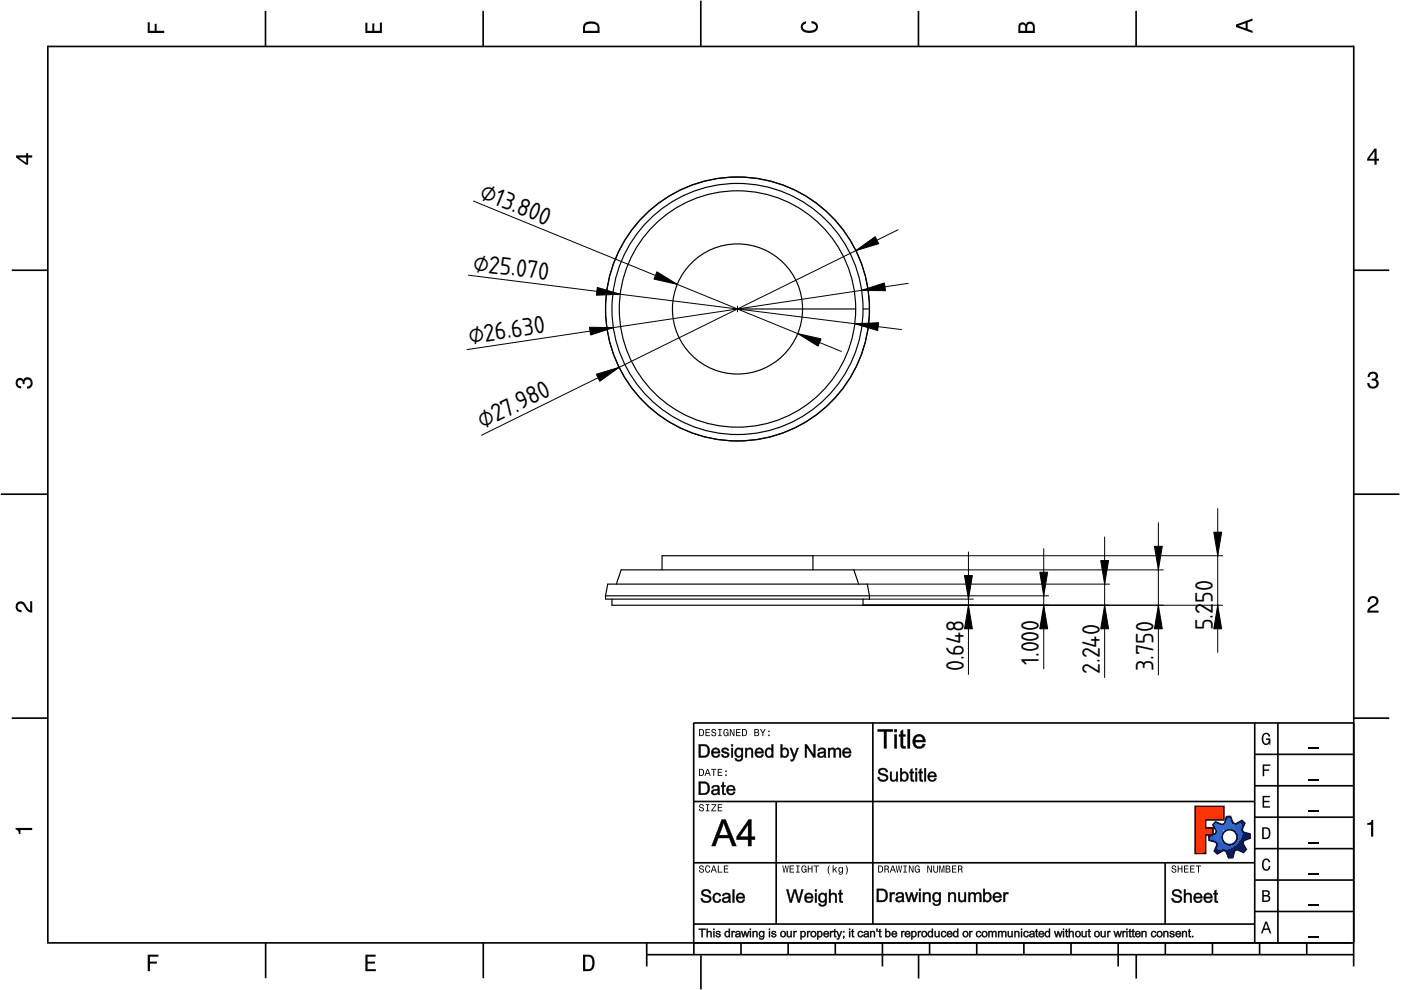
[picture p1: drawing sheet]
<svg xmlns="http://www.w3.org/2000/svg" width="297mm" height="210mm" viewBox="0 0 297 210" stroke-linecap="round" stroke-linejoin="round" font-family="sans-serif">
<defs><g id="words">
<g font-size="5">
<text x="101.5" y="41.9" transform="rotate(22 101.5 41.9)">⌀13.800</text>
<text x="100.2" y="57.4" transform="rotate(7 100.2 57.4)">⌀25.070</text>
<text x="99.6" y="73" transform="rotate(-9 99.6 73)">⌀26.630</text>
<text x="102.3" y="91" transform="rotate(-26 102.3 91)">⌀27.980</text>
<text x="257.2" y="127.9" transform="rotate(-90 257.2 127.9)">50</text>
<text x="257.2" y="133.7" transform="rotate(-90 257.2 133.7)">5.2</text>
<text x="204.3" y="142.3" transform="rotate(-90 204.3 142.3)">0.648</text>
<text x="220.3" y="141" transform="rotate(-90 220.3 141)">1.000</text>
<text x="233.2" y="142.9" transform="rotate(-90 233.2 142.9)">2.240</text>
<text x="244.6" y="142.4" transform="rotate(-90 244.6 142.4)">3.750</text>
</g>
</g></defs>
<g fill="none" stroke="#000" stroke-width=".35">
<path d="M10.1 9.7v190.1M10.1 9.9h277M56.3 2.3v7.5M102.4 2.3v7.5M148.6 .1v9.8M194.7 2.3v7.5M240.9 2.3v7.5M287 9.7v195.2M2.5 57.3h7.5M287.1 57.3h7.4M.2 104.8h10M287 104.8h9.7"/>
<path d="M2.5 152.3h7.5M147 153.3h140.1M147.1 153.3v49.1M185.1 153.2v42.8M266 159.9h21M266 153.3v46.7M270.9 153.3v46.7M287.1 152.3h7.4M147 169.9h119M164.6 169.9v26M266 179.9h21M266 173.3h21"/>
<path d="M266 166.6h21M10 199.9h277.1M56.3 199.9v7.5M102.5 199.9v7.5M137.1 199.9v5M147 195.9h119M147 182.9h119M157.1 199.9v2.5M167.1 199.9v2.5M177.1 199.9v2.5M187.1 199.9v5M197.1 199.9v2.5"/>
<path d="M207.1 199.9v2.5M217.1 199.9v2.5M227.1 199.9v2.5M237.1 199.9v5M247 182.9v13M247.1 199.9v2.5M257.1 199.9v2.5M266 193.3h21M266 186.6h21M267.1 199.9v2.5M277.1 199.9v2.5M137.1 202.4h150"/>
<path d="M148.6 202.6v7.2M194.8 202.4v5.1M240.9 202.4v5.1"/>
</g>
<g fill="#000">
<path d="M31.3 4.7h.4v1.8h1.1v-1.4h.4v1.4h1.6v.5h-3.5z" fill-rule="evenodd"/>
<path d="M77.5 4.8h.4v1.7h1v-1.5h.5v1.5h1.1v-1.7h.5v2.2h-3.5z" fill-rule="evenodd"/>
<path d="M124.1 4.9a2.19 2.19 0 0 0-.5 2.1h3.5v-1.2a1.42 1.42 0 0 0-1.7-1.3zM124.3 5.2a2.14 2.14 0 0 1 2.3 .3l.1 1h-2.7l.1-1z" fill-rule="evenodd"/>
<path d="M170.1 4.9l.8-.4v.5a.7 .7 0 0 0-.7 .5 .7 .7 0 0 0 .3 .8 1.69 1.69 0 0 0 2.5-.6 .9 .9 0 0 0-.9-.8v-.5a1.24 1.24 0 0 1 1.3 1.1 1.24 1.24 0 0 1-1 1.4 2.22 2.22 0 0 1-2.5-.7l-.1-.5z" fill-rule="evenodd"/>
<path d="M216.1 5l-.2 .8v1.2h3.5v-1.3a.98 .98 0 0 0-.7-1.1 .98 .98 0 0 0-1.2 .6 .84 .84 0 0 0-1.4-.2zM216.4 5.3a.54 .54 0 0 1 .7-.1 .54 .54 0 0 1 .3 .6v.7h-1.1zM217.9 5.2a.62 .62 0 0 1 .7-.1 .62 .62 0 0 1 .4 .6v.8h-1.2z" fill-rule="evenodd"/>
<path d="M262.1 5.2v.5l3.5 1.3v-.5l-1.1-.3v-1.4l1.1-.4v-.5zM262.6 5.5l1.5-.6v1.1z" fill-rule="evenodd"/>
<path d="M3.4 32.9v.5l2.1 1.5h.5v-1.5h.8v-.5h-.8v-.5h-.4v.5zM4 33.4h1.6v1.1z" fill-rule="evenodd"/>
<path d="M291.4 31.5l-1.5 2.1v.5h1.5v.8h.5v-.8h.5v-.4h-.5v-2.2zM291.4 32.1v1.6h-1.1z" fill-rule="evenodd"/>
<path d="M3.6 80.4a.86 .86 0 0 1 1.4 .1 1.06 1.06 0 0 1 1.2-.5 1.06 1.06 0 0 1 .7 1.2 1.1 1.1 0 0 1-1.2 1.2v-.4a.71 .71 0 0 0 .8-1 .71 .71 0 0 0-1.3-.1v.6h-.4a.61 .61 0 0 0-.3-.8 .61 .61 0 0 0-.8 .2 .61 .61 0 0 0 .2 .8l.6 .2v.4a1.15 1.15 0 0 1-1.2-.6 1.15 1.15 0 0 1 .3-1.3z" fill-rule="evenodd"/>
<path d="M290.3 79.1a1.08 1.08 0 0 1 1.3-.2 1.08 1.08 0 0 1 .5 1.3l-.4 .2a1.06 1.06 0 0 1 .6 1.3 1.06 1.06 0 0 1-1.2 .7 1.1 1.1 0 0 1-1.2-1.2h.4a.71 .71 0 0 0 1 .8 .71 .71 0 0 0 .1-1.3h-.6v-.4a.61 .61 0 0 0 .8-.3 .61 .61 0 0 0-.2-.8 .61 .61 0 0 0-.8 .2l-.2 .5h-.4z" fill-rule="evenodd"/>
<path d="M3.6 127.8a1.22 1.22 0 0 1 2 .7l.4 .6 .4 .3v-1.9h.4v2.4a1.8 1.8 0 0 1-1.7-1.4 .71 .71 0 0 0-.9-.5 .71 .71 0 0 0-.5 .8 .71 .71 0 0 0 .9 .6v.4a1.18 1.18 0 0 1-1.2-.6 1.18 1.18 0 0 1 .2-1.4z" fill-rule="evenodd"/>
<path d="M290.3 126.7a1.18 1.18 0 0 1 1.9 .3 1.18 1.18 0 0 1-1 1.7l-.5 .3-.3 .5h1.9v.4h-2.4a1.8 1.8 0 0 1 1.4-1.7 .71 .71 0 0 0 .5-.9 .71 .71 0 0 0-.9-.5 .71 .71 0 0 0-.5 .8h-.4z" fill-rule="evenodd"/>
<path d="M148.2 154.6v1.5h.5a.77 .77 0 0 0 .6-.8 .77 .77 0 0 0-.6-.7zM148.4 154.8a.58 .58 0 0 1 .7 .5 .58 .58 0 0 1-.7 .6zM149.6 154.6v1.5h.9v-.2h-.7v-.5h.6v-.2h-.6v-.4h.7v-.2zM151 154.7a.53 .53 0 0 0 0 .6 .53 .53 0 0 0 .6 .2 .32 .32 0 0 1-.3 .5 .32 .32 0 0 1-.3-.4h-.2a.5 .5 0 0 0 .7 .5 .5 .5 0 0 0 .1-.8l-.4-.1a.28 .28 0 0 1-.1-.4 .28 .28 0 0 1 .4-.1 .28 .28 0 0 1 .1 .3h.2a.51 .51 0 0 0-.3-.4 .51 .51 0 0 0-.5 .1zM152.3 154.6v.2h.2v1.1h-.2v.2h.7v-.2h-.3v-1.1h.3v-.2zM153.5 154.7a.81 .81 0 0 0 .5 1.4l.3-.2 .2 .2v-.8h-.6v.1h.4l-.2 .5a.6 .6 0 0 1-.5-.6 .6 .6 0 0 1 .4-.6l.2 .3h.2l-.1-.3a.53 .53 0 0 0-.8 0zM154.7 154.6v1.5h.2v-1.3l.6 1.3h.2v-1.5h-.2v1.2l-.5-1.2zM156.1 154.6v1.5h.9v-.2h-.7v-.5h.6v-.2h-.6v-.4h.7v-.2zM157.3 154.6v1.5h.5a.77 .77 0 0 0 .6-.8 .77 .77 0 0 0-.6-.7zM157.5 154.8a.58 .58 0 0 1 .7 .5 .58 .58 0 0 1-.7 .6zM159.9 154.6v1.5h.6a.42 .42 0 0 0 .5-.3 .42 .42 0 0 0-.3-.5l.2-.2-.1-.4zM160.1 154.8h.3a.23 .23 0 0 1 .3 .2 .23 .23 0 0 1-.3 .2h-.3zM160.1 155.4h.4a.26 .26 0 0 1 .3 .2 .26 .26 0 0 1-.3 .3h-.4zM161.1 154.6l.5 .9v.6h.2v-.6l.5-.9h-.2l-.4 .7-.3-.7zM162.9 155.8v.3h.3v-.3zM162.9 154.9v.3h.3v-.3z" fill-rule="evenodd"/>
<path d="M267.8 155.7a.85 .85 0 0 1 .9-.3 .85 .85 0 0 1 .6 .8h-.3l-.1-.3a.49 .49 0 0 0-.4-.3 .49 .49 0 0 0-.5 .3 1.2 1.2 0 0 0 .4 1.8 .66 .66 0 0 0 .6-.8h-.6v-.3h.9v1.3h-.1l-.1-.3-.3 .3a.85 .85 0 0 1-1.2-.7v-1.1z" fill-rule="evenodd"/>
<path d="M3.3 175.5h3.5v.5h-2.5v.8h-.3a.77 .77 0 0 0-.7-.9z" fill-rule="evenodd"/>
<path d="M148.4 170.6a.53 .53 0 0 0 0 .6 .53 .53 0 0 0 .6 .2 .32 .32 0 0 1-.3 .5 .32 .32 0 0 1-.3-.4h-.2a.5 .5 0 0 0 .7 .6 .5 .5 0 0 0 .1-.9l-.4-.1a.28 .28 0 0 1-.1-.4 .28 .28 0 0 1 .4-.1 .28 .28 0 0 1 .1 .4h.2a.51 .51 0 0 0-.3-.5 .51 .51 0 0 0-.5 .1zM149.7 170.5v.2h.2v1.1h-.2v.2h.7v-.2h-.3v-1.1h.3v-.2zM150.8 170.5v.2h.8l-.8 1.3h1.1v-.2h-.9l.9-1.3zM152.2 170.5v1.5h.9v-.2h-.7v-.5h.6v-.2h-.6v-.4h.7v-.2z" fill-rule="evenodd"/>
<path d="M148.2 163v1.5h.5a.77 .77 0 0 0 .6-.7 .77 .77 0 0 0-.6-.8zM148.4 163.2a.57 .57 0 0 1 .7 .6 .57 .57 0 0 1-.7 .5zM149.9 163l-.5 1.5h.2l.1-.4h.6l.2 .4h.2l-.6-1.5zM150 163.2l.3 .7h-.5zM150.8 163v.2h.4v1.3h.2v-1.3h.5v-.2zM152.2 163v1.5h.9v-.2h-.7v-.5h.6v-.2h-.6v-.4h.7v-.2zM153.8 164.2v.3h.3v-.3zM153.8 163.4v.3h.3v-.3z" fill-rule="evenodd"/>
<path d="M253.4 171h6.1v2.8h-3.9v1.7h1.6v1.5h-1.6v4h-2.2z" fill-rule="evenodd"/>
<path d="M257.7 174.3l-.5 .6 .7 1.3-.2 .6-1.4 .5v.9l1.5 .4 .3 .5-.7 1.4 .7 .5 1.3-.7 .6 .2 .5 1.4 .9-.1 .3-1.4 .6-.3 1.4 .6 .5-.6-.7-1.3 .2-.6 1.4-.5-.1-.9-1.4-.4-.3-.5 .6-1.4-.6-.6-1.3 .8-.6-.2-.5-1.4h-.9l-.4 1.5-.5 .2zM259.1 177.5a1.6 1.6 0 0 1 3.2 0 1.6 1.6 0 0 1-3.2 0z" fill-rule="evenodd"/>
<path d="M267.7 168.7h1.5v.3h-1.2v.8h1.1v.3h-1.1v.8h1.3v.3h-1.6z" fill-rule="evenodd"/>
<path d="M267.7 162.1h1.6v.3h-1.3v.7h1.1v.3h-1.1v1.2h-.3z" fill-rule="evenodd"/>
<path d="M267.6 175.4v2.5h.8a1.37 1.37 0 0 0 .7-2.2 1.56 1.56 0 0 0-1.5-.3zM267.9 175.7a.98 .98 0 0 1 1.2 .7 .98 .98 0 0 1-.7 1.2h-.5z" fill-rule="evenodd"/>
<path d="M289.9 174.5a.77 .77 0 0 0 .9-.6h.4v3.5h-.5v-2.5h-.8z" fill-rule="evenodd"/>
<path d="M148.4 183.6a.53 .53 0 0 0 0 .6 .53 .53 0 0 0 .6 .2 .32 .32 0 0 1-.3 .5 .32 .32 0 0 1-.3-.4h-.2a.5 .5 0 0 0 .7 .6 .5 .5 0 0 0 .1-.9l-.4-.1a.28 .28 0 0 1-.1-.4 .28 .28 0 0 1 .4-.1 .28 .28 0 0 1 .1 .4h.2a.51 .51 0 0 0-.3-.5 .51 .51 0 0 0-.5 .1zM149.6 183.7l-.1 .2a.67 .67 0 0 0 .1 .9 .67 .67 0 0 0 .8 .1l.2-.4h-.2l-.2 .3a.6 .6 0 0 1-.5-.5 .6 .6 0 0 1 .4-.6l.3 .3h.2l-.2-.4a.5 .5 0 0 0-.8 .1zM151.2 183.5l-.5 1.5h.2l.1-.4h.6l.2 .4h.2l-.6-1.5zM151.3 183.7l.3 .7h-.5zM152.2 183.5v1.5h1v-.2h-.8v-1.3zM153.5 183.5v1.5h.9v-.2h-.7v-.5h.6v-.2h-.6v-.4h.7v-.2z" fill-rule="evenodd"/>
<path d="M165.9 183.5l.3 1.5h.1l.3-1.3 .2 1.3h.2l.2-1.5h-.1l-.2 1.3-.2-1.3h-.2l-.2 1.3-.2-1.3zM167.4 183.5v1.5h1v-.2h-.8v-.5h.7v-.2h-.7v-.4h.7v-.2zM168.8 183.5v.2h.3v1.1h-.3v.2h.7v-.2h-.2v-1.1h.2v-.2zM170.1 183.7a.82 .82 0 0 0 .5 1.3l.3-.2 .1 .2v-.8h-.5v.2h.3l-.2 .4a.6 .6 0 0 1-.5-.5 .6 .6 0 0 1 .5-.6l.2 .3h.2l-.2-.4a.53 .53 0 0 0-.7 .1zM171.3 183.5v1.5h.2v-.7h.6v.7h.2v-1.5h-.2v.6h-.6v-.6zM172.5 183.5v.2h.5v1.3h.2v-1.3h.4v-.2zM175.8 183.5a1.35 1.35 0 0 0 .2 1.9 1.84 1.84 0 0 1 0-1.9zM176.5 183.5v1.5h.2v-.4l.2-.2 .4 .6h.2l-.4-.7 .4-.5h-.2l-.6 .6v-.9zM177.9 184a.59 .59 0 0 0-.2 .7 .59 .59 0 0 0 .7 .3l.1-.2a.31 .31 0 0 1-.1 .5 .31 .31 0 0 1-.4-.2h-.2a.47 .47 0 0 0 .5 .4 .47 .47 0 0 0 .4-.5v-1.2h-.2v.2l-.3-.2zM178 184.1l.1-.1a.42 .42 0 0 1 .4 .4 .42 .42 0 0 1-.4 .5l-.1-.3zM179.3 183.5a1.85 1.85 0 0 1 0 1.9 1.22 1.22 0 0 0 0-1.9z" fill-rule="evenodd"/>
<path d="M186.2 183.5v1.5h.5a.77 .77 0 0 0 .6-.7 .77 .77 0 0 0-.6-.8zM186.4 183.7a.58 .58 0 0 1 .6 .6 .58 .58 0 0 1-.6 .5zM187.5 183.5v1.5h.2v-.6a.45 .45 0 0 1 .5 .1 .45 .45 0 0 1 .1 .5h.2l-.2-.7a.42 .42 0 0 0 .1-.5 .42 .42 0 0 0-.4-.3zM187.7 183.7h.2a.26 .26 0 0 1 .4 .3 .26 .26 0 0 1-.4 .2h-.2zM189.2 183.5l-.6 1.5h.2l.2-.4h.6l.1 .4h.2l-.5-1.5zM189.3 183.7l.2 .7h-.4zM189.9 183.5l.3 1.5h.2l.2-1.3 .2 1.3h.2l.3-1.5h-.2l-.2 1.3-.2-1.3h-.2l-.2 1.3-.2-1.3zM191.5 183.5v.2h.3v1.1h-.3v.2h.8v-.2h-.3v-1.1h.3v-.2zM192.7 183.5v1.5h.2v-1.2l.5 1.2h.3v-1.5h-.2v1.2l-.6-1.2zM194.1 183.7a.81 .81 0 0 0 .5 1.3l.3-.2 .1 .2v-.8h-.5v.2h.3l-.2 .4a.6 .6 0 0 1-.5-.5 .6 .6 0 0 1 .5-.6l.2 .3h.2l-.2-.4a.53 .53 0 0 0-.7 .1zM196.6 183.5v1.5h.2v-1.2l.6 1.2h.2v-1.5h-.2v1.2l-.6-1.2zM197.9 183.5v.9a.52 .52 0 0 0 .5 .6 .52 .52 0 0 0 .5-.6v-.9h-.2v.9a.33 .33 0 0 1-.3 .5 .33 .33 0 0 1-.3-.5v-.9zM199.2 183.5v1.5h.1v-1.4l.3 1.4h.2l.3-1.4v1.4h.1v-1.5h-.2l-.3 1.3-.3-1.3zM200.5 183.5v1.5h.6a.42 .42 0 0 0 .4-.3 .42 .42 0 0 0-.2-.5l.2-.2-.1-.4zM200.7 183.7h.3a.23 .23 0 0 1 .3 .2 .23 .23 0 0 1-.3 .2h-.3zM200.7 184.3h.3a.26 .26 0 0 1 .3 .3 .26 .26 0 0 1-.3 .2h-.3zM201.8 183.5v1.5h1v-.2h-.8v-.5h.7v-.2h-.7v-.4h.8v-.2zM203.1 183.5v1.5h.2v-.6a.45 .45 0 0 1 .5 .1 .45 .45 0 0 1 .1 .5h.2l-.2-.7a.42 .42 0 0 0 .1-.5 .42 .42 0 0 0-.4-.3zM203.3 183.7h.3a.26 .26 0 0 1 .3 .3 .26 .26 0 0 1-.4 .2h-.2z" fill-rule="evenodd"/>
<path d="M248.5 183.6a.53 .53 0 0 0 0 .6 .53 .53 0 0 0 .6 .2 .32 .32 0 0 1-.2 .5 .32 .32 0 0 1-.3-.4h-.2a.5 .5 0 0 0 .6 .6 .5 .5 0 0 0 .2-.9l-.4-.1a.28 .28 0 0 1-.1-.4 .28 .28 0 0 1 .3-.1 .28 .28 0 0 1 .2 .4h.2a.51 .51 0 0 0-.3-.5 .51 .51 0 0 0-.6 .1zM249.7 183.5v1.5h.2v-.7h.6v.7h.2v-1.5h-.2v.6h-.6v-.6zM251 183.5v1.5h1v-.2h-.8v-.5h.7v-.2h-.7v-.4h.8v-.2zM252.3 183.5v1.5h1v-.2h-.8v-.5h.7v-.2h-.7v-.4h.8v-.2zM253.5 183.5v.2h.5v1.3h.2v-1.3h.5v-.2z" fill-rule="evenodd"/>
<path d="M268.3 195.4l-1 2.5h.4l.2-.7h1l.3 .7h.3l-.9-2.5zM268.4 195.8l.4 1.1h-.7z" fill-rule="evenodd"/>
<path d="M267.6 188.7v2.5h1a.7 .7 0 0 0 .7-.5 .7 .7 0 0 0-.4-.8 .61 .61 0 0 0 .3-.8 .61 .61 0 0 0-.7-.4zM267.9 189h.6a.38 .38 0 0 1 .4 .4 .38 .38 0 0 1-.5 .4h-.5zM267.9 190.1h.6a.44 .44 0 0 1 .5 .4 .44 .44 0 0 1-.5 .4h-.6z" fill-rule="evenodd"/>
<path d="M267.8 182.3a.85 .85 0 0 1 .9-.3 .85 .85 0 0 1 .6 .8h-.3l-.1-.2a.47 .47 0 0 0-.4-.3 .47 .47 0 0 0-.4 .3 1.21 1.21 0 0 0 .4 1.7 .64 .64 0 0 0 .5-.7h.4a.89 .89 0 0 1-.8 1 .89 .89 0 0 1-1-.7v-1.1z" fill-rule="evenodd"/>
<path d="M31.3 202.4h2.3v.4h-1.8v1.1h1.5v.4h-1.5v1.6h-.5z" fill-rule="evenodd"/>
<path d="M77.5 202.4h2.1v.4h-1.7v1.1h1.6v.4h-1.6v1.2h1.8v.4h-2.2z" fill-rule="evenodd"/>
<path d="M123.6 202.4v3.5h1.2a1.42 1.42 0 0 0 1.3-1.7 1.38 1.38 0 0 0-1.3-1.8zM124.1 202.8l1 .1a1.89 1.89 0 0 1 0 2.5l-1 .1z" fill-rule="evenodd"/>
</g>
<path d="M277.3 158.6h2.2M277.3 178.6h2.2M277.3 172h2.2M277.3 165.3h2.2M277.3 198.6h2.2M277.3 192h2.2M277.3 185.3h2.2" fill="none" stroke="#000" stroke-width=".25"/>
<g fill="#000">
<path d="M186.1 154.6h3.2v.6l-1.3-.1v3.6h-.6v-3.6l-1.3 .1zM186.1 154.6v.5h1.4l-.1 3.6h.6l-.1-3.6h1.4v-.5zM189.6 154.6h.6v.7h-.6zM189.6 154.6v.6h.5v-.6zM189.6 155.7h.6v3h-.6zM189.6 155.7v3h.5v-3zM190.9 155l.6-.3v1h.5v.5l-.5-.1v1.7a.31 .31 0 0 0 .1 .4 .31 .31 0 0 0 .4 0l.1 .5a.79 .79 0 0 1-.9-.1 .79 .79 0 0 1-.3-.8l.1-1.7-.4 .1v-.5h.4zM191 155v.8l-.4-.1v.4h.4v1.7a.68 .68 0 0 0 .2 .8 .68 .68 0 0 0 .8 0v-.4a.35 .35 0 0 1-.5 0 .35 .35 0 0 1-.1-.4v-1.7h.6v-.4l-.6 .1 .1-1.1zM192.4 154.6h.6v4.1h-.6zM192.4 154.6v4.1h.5v-4.1zM193.9 156.1a1.38 1.38 0 0 1 1.6-.3 1.38 1.38 0 0 1 .7 1.6l-2.1-.1a.83 .83 0 0 0 .6 1 .83 .83 0 0 0 1-.6h.5a1.2 1.2 0 0 1-1.6 1 1.62 1.62 0 0 1-.7-2.6zM193.9 156.1a1.47 1.47 0 0 0-.1 2 1.47 1.47 0 0 0 1.9 .3l.5-.6-.5-.1a.85 .85 0 0 1-1.1 .6 .85 .85 0 0 1-.6-1h2.2a1.32 1.32 0 0 0-.7-1.4 1.32 1.32 0 0 0-1.6 .2zM194.3 156.3l-.2 .6h1.5a.76 .76 0 0 0-.4-.7 .76 .76 0 0 0-.9 .1zM194.3 156.3l.6-.3 .4 .2 .3 .3 .1 .5h-1.7z"/>
<path d="M186.1 154.6h3.2v.5h-1.3v3.6h-.6v-3.6h-1.3zM189.6 154.6h.5v.6h-.5zM189.6 155.7h.5v3h-.5zM191 155l.5-.3v1h.5v.4h-.5v1.7a.33 .33 0 0 0 .1 .4 .33 .33 0 0 0 .4 0v.5a.73 .73 0 0 1-.8-.1 .73 .73 0 0 1-.2-.8v-1.7h-.4v-.4h.4zM192.4 154.6h.5v4.1h-.5zM193.9 156.1a1.36 1.36 0 0 1 1.6-.3 1.36 1.36 0 0 1 .7 1.5h-2.2a.85 .85 0 0 0 .7 1 .85 .85 0 0 0 1-.6l.5 .1a1.43 1.43 0 0 1-2 .8 1.43 1.43 0 0 1-.6-2zM194.3 156.3l-.2 .6h1.6a.8 .8 0 0 0-.5-.7 .8 .8 0 0 0-.9 .1z"/>
<path d="M148.1 157.8h1.4l.5 .3a1.41 1.41 0 0 1 .5 1.5 1.17 1.17 0 0 1-1.3 1h-1.1zM148.2 157.8v2.8h1a1.42 1.42 0 0 0 1.2-1 1.42 1.42 0 0 0-.4-1.5l-.5-.2zM148.5 158.2v2.1l.6-.1a1.08 1.08 0 0 0 1-.8 1.08 1.08 0 0 0-.5-1.1zM148.5 158.1h.6a1.13 1.13 0 0 1 1 1 1.13 1.13 0 0 1-.7 1.2h-.9zM151 158.8a.96 .96 0 0 1 1.2-.2 .96 .96 0 0 1 .5 1.1h-1.5a.56 .56 0 0 0 .4 .6 .56 .56 0 0 0 .7-.4l.4 .1a.83 .83 0 0 1-1.2 .7 1.16 1.16 0 0 1-.5-1.9zM151.1 158.9a1 1 0 0 0-.1 1.4 1 1 0 0 0 1.4 0l.3-.3h-.4a.59 .59 0 0 1-.7 .4 .59 .59 0 0 1-.4-.8l1.5 .1a1.1 1.1 0 0 0-.9-1.1zM151.4 159l-.2 .4h1.1a.51 .51 0 0 0-.3-.5 .51 .51 0 0 0-.6 .1zM151.3 159l.5-.2 .3 .1 .3 .5h-1.3zM153.1 158.7h.1a.85 .85 0 0 1 1.4 .4l-.4 .1a.41 .41 0 0 0-.4-.3 .41 .41 0 0 0-.4 .3l.4 .2a.68 .68 0 0 1 .9 .6 .68 .68 0 0 1-.9 .7 .71 .71 0 0 1-.9-.7l.4-.1a.5 .5 0 0 0 .4 .4 .5 .5 0 0 0 .5-.3l-.2-.1a.92 .92 0 0 1-1-.9zM153.2 158.8a.6 .6 0 0 0 0 .7 .6 .6 0 0 0 .6 .2l.5 .2a.5 .5 0 0 1-.5 .5 .5 .5 0 0 1-.5-.5l-.4 .1a.82 .82 0 0 0 .9 .6 .82 .82 0 0 0 .7-.7l-.2-.3-1-.4a.48 .48 0 0 1 .5-.4 .48 .48 0 0 1 .4 .4l.3-.1a.88 .88 0 0 0-1.3-.3zM155 157.8h.4v.5h-.4zM155.1 157.8v.4h.3v-.4zM155 158.6h.4v2h-.4zM155.1 158.6v2h.3v-2zM156 158.8a.77 .77 0 0 1 1.2 0v-.2h.4v1.7a.91 .91 0 0 1-.7 1.1 .91 .91 0 0 1-1.1-.7l.3 .1a.53 .53 0 0 0 .5 .3 .53 .53 0 0 0 .5-.3l.1-.5a.81 .81 0 0 1-.9 .3 .81 .81 0 0 1-.6-.7l.1-.7zM156.1 158.8a.93 .93 0 0 0-.2 1.3 .93 .93 0 0 0 1.2 .2h.1a.61 .61 0 0 1-.2 .8 .61 .61 0 0 1-.7-.1l-.2-.2h-.3a.86 .86 0 0 0 1.1 .5 .86 .86 0 0 0 .6-1v-1.7h-.3v.4a.76 .76 0 0 0-1.1-.2zM156.3 159a.65 .65 0 0 0-.2 .9 .65 .65 0 0 0 .9 .2 .65 .65 0 0 0 .1-.9 .65 .65 0 0 0-.8-.2zM156.2 159a.74 .74 0 0 1 1.1 .4 .74 .74 0 0 1-.7 1 .82 .82 0 0 1-.4-1.4zM158 158.6h.4l-.1 .3a.73 .73 0 0 1 .9-.4 .73 .73 0 0 1 .5 .9v1.2h-.4v-1.2a.46 .46 0 0 0-.5-.5 .46 .46 0 0 0-.4 .6v1.1h-.4zM158 158.6v2h.4l-.1-1.1a.53 .53 0 0 1 .5-.7 .53 .53 0 0 1 .6 .6l-.1 1.2h.4l-.1-1.6a.73 .73 0 0 0-.6-.4 .73 .73 0 0 0-.7 .4v-.4zM160.3 158.8a.96 .96 0 0 1 1.2-.2 .96 .96 0 0 1 .4 1.1h-1.5a.56 .56 0 0 0 .5 .6 .56 .56 0 0 0 .6-.4l.4 .1a.83 .83 0 0 1-1.2 .7 1.16 1.16 0 0 1-.4-1.9zM160.3 158.9a1 1 0 0 0 0 1.4 1 1 0 0 0 1.4 0l.2-.3h-.4a.59 .59 0 0 1-.7 .4 .59 .59 0 0 1-.4-.8l1.5 .1a1.1 1.1 0 0 0-.9-1.1zM160.6 159l-.2 .4h1.1a.51 .51 0 0 0-.3-.5 .51 .51 0 0 0-.6 .1zM160.6 159l.4-.2 .3 .1 .3 .5h-1.2zM162.4 158.7a.74 .74 0 0 1 1.2 .1l-.1-1h.5v2.8h-.4v-.3a.74 .74 0 0 1-1.3 0 1.38 1.38 0 0 1 .1-1.6zM162.5 158.8a.98 .98 0 0 0-.2 1.2 .98 .98 0 0 0 1.1 .5l.3-.3-.1 .4h.3v-2.8h-.3v1.2a.71 .71 0 0 0-1.1-.2zM162.7 159a.67 .67 0 0 0-.1 .9 .67 .67 0 0 0 .8 .3 .67 .67 0 0 0 .2-.9 .67 .67 0 0 0-.9-.3zM162.7 159a.66 .66 0 0 1 .8 0 .66 .66 0 0 1 .1 .9 .59 .59 0 0 1-.7 .5 .59 .59 0 0 1-.4-.8zM165.5 157.8h.4v1a.78 .78 0 0 1 .8-.3 .78 .78 0 0 1 .5 .6 .96 .96 0 0 1-.1 1.3 .96 .96 0 0 1-1.3 0l.1 .2h-.4zM165.5 157.8v2.8h.3v-.4a.83 .83 0 0 0 1.1 .3 .83 .83 0 0 0 .3-1.1 .76 .76 0 0 0-.5-.8 .76 .76 0 0 0-.9 .3l.1-1.1zM166 159a.71 .71 0 0 0-.1 .9 .71 .71 0 0 0 .7 .4 .74 .74 0 0 0 .3-.8 .74 .74 0 0 0-.7-.6zM166 159a.65 .65 0 0 1 .8 0 .65 .65 0 0 1 .1 .8 .53 .53 0 0 1-.4 .6 .53 .53 0 0 1-.6-.3l-.1-.5zM167.4 158.6h.5l.5 1.6 .5-1.6h.5l-1 2.5a.49 .49 0 0 1-.8 .3v-.4l.5-.1 .1-.3zM167.5 158.6l.8 2-.3 .5h-.4l.1 .2a.7 .7 0 0 0 .8-.7l.8-2h-.3l-.6 1.6-.6-1.6zM170.6 157.8h.5l1.4 2.2v-2.2h.4v2.8h-.4l-1.5-2.2 .1 2.2h-.5zM170.7 157.8v2.8h.3v-2.3l1.5 2.3h.4v-2.8h-.4v2.3l-1.4-2.3zM173.5 158.8a.88 .88 0 0 1 1-.3 .88 .88 0 0 1 .6 .8l.1 1.3h-.4v-.2a.73 .73 0 0 1-1.1 .3 .73 .73 0 0 1-.2-1.1l1.2-.3a.49 .49 0 0 0-.5-.4 .49 .49 0 0 0-.5 .4l-.4-.1zM173.6 158.8l-.2 .4h.3a.52 .52 0 0 1 .4-.4 .52 .52 0 0 1 .5 .1l.2 .5-1 .1a.6 .6 0 0 0-.3 1 .99 .99 0 0 0 1.3-.2v.3h.4l-.2-.4v-1.2a.97 .97 0 0 0-1.4-.2zM173.8 159.9a.43 .43 0 0 0 .3 .5 .43 .43 0 0 0 .5-.4l.1-.4zM173.8 159.8l1-.3a.62 .62 0 0 1-.3 .8 .62 .62 0 0 1-.9-.2zM175.5 158.6h.4v.3a.68 .68 0 0 1 .6-.4 .68 .68 0 0 1 .6 .4 .67 .67 0 0 1 .7-.4 .67 .67 0 0 1 .5 .7v1.4h-.4v-1.3a.41 .41 0 0 0-.4-.4 .41 .41 0 0 0-.3 .5v1.2h-.5v-1.3a.42 .42 0 0 0-.5-.4 .42 .42 0 0 0-.2 .7v1h-.5zM175.6 158.6v2h.3v-1a.5 .5 0 0 1 .3-.8 .5 .5 0 0 1 .6 .5v1.3h.3v-1.2a.48 .48 0 0 1 .4-.6 .48 .48 0 0 1 .5 .5v1.3h.3v-1.4a.62 .62 0 0 0-.5-.6 .62 .62 0 0 0-.7 .4 .65 .65 0 0 0-.7-.4 .65 .65 0 0 0-.6 .4l.1-.4zM178.8 158.8a.96 .96 0 0 1 1.2-.2 .96 .96 0 0 1 .5 1.1h-1.5a.56 .56 0 0 0 .4 .6 .56 .56 0 0 0 .7-.4l.3 .1a.83 .83 0 0 1-1.1 .7 1.16 1.16 0 0 1-.5-1.9zM178.9 158.9a1 1 0 0 0-.1 1.4 1 1 0 0 0 1.4 0l.2-.3h-.3a.59 .59 0 0 1-.7 .4 .59 .59 0 0 1-.4-.8l1.5 .1a1.1 1.1 0 0 0-1-1.1zM179.2 159l-.2 .4h1.1a.51 .51 0 0 0-.3-.5 .51 .51 0 0 0-.6 .1zM179.1 159l.4-.2 .4 .1 .2 .5h-1.2z"/>
<path d="M148.1 165.7h1.4l.5 .3a1.41 1.41 0 0 1 .5 1.5 1.17 1.17 0 0 1-1.3 1.1h-1.1zM148.2 165.7v2.8h1a1.42 1.42 0 0 0 1.2-1 1.42 1.42 0 0 0-.4-1.5l-.5-.2zM148.5 166.1v2.1h.6a1.08 1.08 0 0 0 1-.9 1.08 1.08 0 0 0-.5-1.1zM148.5 166h.6a1.13 1.13 0 0 1 1 1 1.13 1.13 0 0 1-.7 1.2h-.9zM151 166.7a.88 .88 0 0 1 1-.3 .88 .88 0 0 1 .6 .8l.1 1.4h-.4l-.1-.3a.73 .73 0 0 1-1 .3 .73 .73 0 0 1-.2-1.1l1.2-.3a.49 .49 0 0 0-.5-.4 .49 .49 0 0 0-.5 .4l-.4-.1zM151.1 166.8l-.2 .3h.3a.52 .52 0 0 1 .4-.4 .52 .52 0 0 1 .5 .2l.1 .4-.9 .1a.6 .6 0 0 0-.3 1 .99 .99 0 0 0 1.3-.2v.3h.4l-.2-.3v-1.3a.97 .97 0 0 0-1.4-.1zM151.3 167.8a.43 .43 0 0 0 .3 .5 .43 .43 0 0 0 .5-.3l.1-.5zM151.3 167.7l.9-.2a.57 .57 0 0 1-.3 .8 .57 .57 0 0 1-.8-.4zM153.1 166l.4-.3v.8h.4v.3h-.4v1.3l.3 .1 .1 .3a.57 .57 0 0 1-.6 0 .57 .57 0 0 1-.2-.6v-1.1h-.3v-.3h.3zM153.1 166l.1 .6-.3-.1v.3l.3-.1v1.2a.46 .46 0 0 0 .1 .5 .46 .46 0 0 0 .6 .1l-.1-.2a.27 .27 0 0 1-.3-.1 .27 .27 0 0 1-.1-.3v-1.2l.4 .1v-.3l-.4 .1 .1-.8zM154.3 166.7a.96 .96 0 0 1 1.1-.2 .96 .96 0 0 1 .5 1.1h-1.5a.56 .56 0 0 0 .5 .6 .56 .56 0 0 0 .6-.4l.4 .1a.83 .83 0 0 1-1.2 .7 1.16 1.16 0 0 1-.4-1.9zM154.3 166.8a1 1 0 0 0-.1 1.4 1 1 0 0 0 1.5 0l.2-.3h-.4a.59 .59 0 0 1-.7 .4 .59 .59 0 0 1-.4-.7h1.5a1.1 1.1 0 0 0-.9-1.1zM154.6 166.9l-.2 .4h1.1a.51 .51 0 0 0-.3-.5 .51 .51 0 0 0-.6 .1zM154.5 166.9l.5-.2 .3 .1 .3 .6h-1.2z"/>
<path d="M148.2 157.8h.9a1.41 1.41 0 0 1 1.4 1.3 1.41 1.41 0 0 1-1 1.5h-1.3zM148.5 158.2v2.1h.6a1.06 1.06 0 0 0 1-1.1 1.06 1.06 0 0 0-1-1zM151.1 158.8a.94 .94 0 0 1 1.1-.1 .94 .94 0 0 1 .5 1h-1.5a.59 .59 0 0 0 .4 .6 .59 .59 0 0 0 .7-.3h.4a1 1 0 0 1-1.5 .5 1 1 0 0 1-.3-1.5zM151.4 159l-.2 .4h1.1a.56 .56 0 0 0-.3-.5 .56 .56 0 0 0-.6 .1zM153.1 158.8a.87 .87 0 0 1 1.4 .3l-.3 .1a.4 .4 0 0 0-.5-.4 .4 .4 0 0 0-.3 .5h.2a.86 .86 0 0 1 1 .9 .89 .89 0 0 1-.9 .4 .89 .89 0 0 1-.8-.6l.4-.1a.45 .45 0 0 0 .5 .5 .45 .45 0 0 0 .4-.5l-.2-.1a.89 .89 0 0 1-1-.8zM155.1 157.8h.3v.4h-.3zM155.1 158.6h.3v2h-.3zM156 158.8l.6-.3 .6 .3v-.2h.3v1.7a.88 .88 0 0 1-.6 1.1 .88 .88 0 0 1-1.1-.6h.3a.57 .57 0 0 0 .8 .3 .57 .57 0 0 0 .3-.8 .97 .97 0 0 1-1.3-.2 .97 .97 0 0 1 .1-1.3zM156.3 159a.72 .72 0 0 0-.2 .9 .72 .72 0 0 0 .8 .3 .7 .7 0 0 0 .3-.9 .7 .7 0 0 0-.9-.3zM158 158.6h.3v.3a.72 .72 0 0 1 .9-.3 .72 .72 0 0 1 .5 .8v1.2h-.4v-1.2a.5 .5 0 0 0-.5-.6 .5 .5 0 0 0-.4 .7v1.1h-.4zM160.3 158.8a.94 .94 0 0 1 1.1-.1 .94 .94 0 0 1 .5 1h-1.5a.59 .59 0 0 0 .4 .6 .59 .59 0 0 0 .7-.3h.4a1 1 0 0 1-1.4 .5 1 1 0 0 1-.3-1.5zM160.6 159l-.2 .4h1.1a.56 .56 0 0 0-.3-.5 .56 .56 0 0 0-.6 .1zM162.5 158.8a.75 .75 0 0 1 1.1 0v-1h.3v2.8h-.3v-.3a.9 .9 0 0 1-1.2 .1 .9 .9 0 0 1-.2-1.2zM162.7 159a.74 .74 0 0 0-.2 .9 .74 .74 0 0 0 .8 .4 .75 .75 0 0 0 .4-.9 .75 .75 0 0 0-.9-.5zM165.5 157.8h.4v1a.88 .88 0 0 1 1.1 0 .88 .88 0 0 1 .2 1.1 .79 .79 0 0 1-.5 .7 .79 .79 0 0 1-.9-.2v.2h-.3zM166 159a.73 .73 0 0 0-.2 .9 .73 .73 0 0 0 .8 .4 .74 .74 0 0 0 .4-.9 .74 .74 0 0 0-.9-.5zM167.5 158.6h.3l.6 1.6 .6-1.6h.3l-.7 2a.74 .74 0 0 1-.9 .8l-.1-.3a.45 .45 0 0 0 .6-.5zM170.7 157.8h.4l1.4 2.2v-2.2h.4v2.8h-.4l-1.5-2.2v2.2h-.3zM173.5 158.8a.87 .87 0 0 1 1-.3 .87 .87 0 0 1 .6 .8l.1 1.3h-.4v-.2a.74 .74 0 0 1-1 .3 .74 .74 0 0 1-.4-.9l.4-.3 .9-.2a.51 .51 0 0 0-.4-.5 .51 .51 0 0 0-.6 .4h-.3zM173.8 159.8a.36 .36 0 0 0 0 .5 .36 .36 0 0 0 .5 .1l.4-.3v-.5zM175.6 158.6h.3v.3a.68 .68 0 0 1 1.2 0 .65 .65 0 0 1 .7-.3 .65 .65 0 0 1 .5 .6v1.4h-.3v-1.3a.45 .45 0 0 0-.5-.5 .45 .45 0 0 0-.4 .6v1.2h-.3v-1.3a.46 .46 0 0 0-.6-.4 .46 .46 0 0 0-.3 .7v1h-.3zM178.9 158.8a.94 .94 0 0 1 1.1-.1 .94 .94 0 0 1 .5 1h-1.5a.59 .59 0 0 0 .4 .6 .59 .59 0 0 0 .7-.3h.3a1 1 0 0 1-1.4 .5 1 1 0 0 1-.3-1.5zM179.2 159l-.2 .4h1.1a.56 .56 0 0 0-.3-.5 .56 .56 0 0 0-.6 .1z"/>
<path d="M148.2 165.7h.9a1.41 1.41 0 0 1 1.4 1.3 1.41 1.41 0 0 1-1 1.5h-1.3zM148.5 166.1v2.1h.6a1.06 1.06 0 0 0 1-1.1 1.06 1.06 0 0 0-1-1zM151 166.7a.87 .87 0 0 1 1-.2 .87 .87 0 0 1 .6 .7l.1 1.3h-.4l-.1-.2a.74 .74 0 0 1-.9 .3 .74 .74 0 0 1-.4-.9l.4-.3 .9-.2a.51 .51 0 0 0-.4-.5 .51 .51 0 0 0-.6 .4h-.3zM151.3 167.8a.36 .36 0 0 0 0 .4 .36 .36 0 0 0 .5 .1l.4-.3v-.5zM153.1 166l.4-.2v.7h.3v.3h-.3v1.1v.3h.3l.1 .3a.5 .5 0 0 1-.6 0 .5 .5 0 0 1-.2-.6v-1.1h-.2v-.3h.2zM154.3 166.7a.94 .94 0 0 1 1.1-.1 .94 .94 0 0 1 .5 1h-1.5a.59 .59 0 0 0 .4 .7 .59 .59 0 0 0 .7-.4h.4a1 1 0 0 1-1.4 .5 1 1 0 0 1-.4-1.4zM154.6 166.9l-.2 .4h1.1a.56 .56 0 0 0-.3-.5 .56 .56 0 0 0-.6 .1z"/>
<path d="M153 173.7h.9l2.3 5.7h-1l-.6-1.7h-2.3l-.6 1.7h-.9zM153 173.8l-2.1 5.6h.8l.5-1.8h2.5l.6 1.8h.8l-2.3-5.6zM153.4 174.4l-.2 .8-.7 1.9h1.9zM153.4 174.3l1.1 2.8h-2.1zM158.7 173.7h.6v3.7h.8v.7l-.8-.1v1.4h-.7v-1.4l-2.5 .1v-.7zM158.7 173.8l-2.5 3.6v.6h2.5l-.1 1.4h.7v-1.4h.8v-.6h-.8v-3.6zM158.6 174.9l-1.7 2.5h1.7zM158.7 174.7v2.7h-1.9z"/>
<path d="M153 173.8h.8l2.3 5.6h-.8l-.7-1.7h-2.3l-.6 1.7h-.8zM153.4 174.4l-.9 2.7h1.9zM158.7 173.8h.6v3.6h.8v.6h-.8v1.4h-.7v-1.4h-2.4v-.6zM158.6 174.9l-1.7 2.5h1.7z"/>
<path d="M186.4 163.1a1.12 1.12 0 0 1 1.9 .6h-.4a.64 .64 0 0 0-.6-.5 .64 .64 0 0 0-.7 .5l.6 .3a.93 .93 0 0 1 1.1 1 .93 .93 0 0 1-1.3 .7 .91 .91 0 0 1-.9-1h.3a.75 .75 0 0 0 .7 .6 .75 .75 0 0 0 .8-.5l-1.3-.6a.67 .67 0 0 1-.2-1.1zM186.5 163.1a.75 .75 0 0 0-.1 .8 .75 .75 0 0 0 .7 .4l.5 .2a.49 .49 0 0 1 .4 .7 .49 .49 0 0 1-.7 .2 .69 .69 0 0 1-.9-.7l-.3 .1a1.12 1.12 0 0 0 1 .9 1.12 1.12 0 0 0 1.2-.8l-.2-.4-.3-.3-1.2-.3a.63 .63 0 0 1 .4-.8 .63 .63 0 0 1 .8 .3l.1 .3h.3a1.02 1.02 0 0 0-1.7-.6zM188.7 163.6h.4v1.5a.49 .49 0 0 0 .6 .2 .49 .49 0 0 0 .3-.6v-1.1h.4v2.1h-.4v-.3a.73 .73 0 0 1-.7 .3 .73 .73 0 0 1-.6-.5zM188.7 163.7l.1 1.2a.68 .68 0 0 0 .5 .8 .68 .68 0 0 0 .8-.5l-.1 .5h.3v-2h-.3v1a.55 .55 0 0 1-.4 .8 .55 .55 0 0 1-.6-.7l.1-1.1zM190.8 162.8h.4v1.1a.78 .78 0 0 1 .8-.3 .78 .78 0 0 1 .6 .6 .96 .96 0 0 1-.2 1.2 .96 .96 0 0 1-1.3 0l.1 .3h-.4zM190.9 162.9v2.8h.3l-.1-.4a.83 .83 0 0 0 1.2 .2 .83 .83 0 0 0 .3-1.1 .76 .76 0 0 0-.6-.7 .76 .76 0 0 0-.8 .3v-1.1zM191.4 164.1a.71 .71 0 0 0-.2 .8 .71 .71 0 0 0 .7 .4 .74 .74 0 0 0 .3-.8 .74 .74 0 0 0-.7-.5zM191.3 164.1a.65 .65 0 0 1 .9-.1 .65 .65 0 0 1 .1 .9 .53 .53 0 0 1-.4 .5 .53 .53 0 0 1-.6-.2l-.2-.6zM193 163.1l.5-.2-.1 .8 .4-.1v.4h-.4l.1 1.3h.3l.1 .4a.57 .57 0 0 1-.7-.1 .57 .57 0 0 1-.2-.5l.1-1.2-.3 .1v-.4l.3 .1zM193.1 163.2v.5h-.3v.2h.3v1.2a.46 .46 0 0 0 .2 .5 .46 .46 0 0 0 .5 0v-.2a.27 .27 0 0 1-.3 0 .27 .27 0 0 1-.1-.3v-1.2h.4v-.2h-.4v-.7zM194 162.8h.5v.5h-.5zM194.1 162.9v.4h.3v-.4zM194 163.6h.5v2.1h-.5zM194.1 163.7v2h.3v-2zM194.9 163.1l.5-.2-.1 .8 .4-.1v.4h-.4l.1 1.3h.3l.1 .4a.57 .57 0 0 1-.7-.1 .57 .57 0 0 1-.2-.5l.1-1.2-.3 .1v-.4l.3 .1zM195 163.2v.5h-.3v.2h.3v1.2a.46 .46 0 0 0 .2 .5 .46 .46 0 0 0 .5 0v-.2a.27 .27 0 0 1-.3 0 .27 .27 0 0 1-.1-.3v-1.2h.4v-.2h-.4v-.7zM195.9 162.8h.5v2.9h-.5zM196 162.9v2.8h.3v-2.8zM196.9 163.9a.96 .96 0 0 1 1.2-.2 .96 .96 0 0 1 .4 1.1l-1.4-.1a.56 .56 0 0 0 .4 .7 .56 .56 0 0 0 .7-.4h.3a.83 .83 0 0 1-1.1 .7 1.16 1.16 0 0 1-.5-1.8zM197 163.9a1 1 0 0 0-.1 1.4 1 1 0 0 0 1.4 .1l.2-.3-.3-.1a.59 .59 0 0 1-.7 .4 .59 .59 0 0 1-.5-.7h1.5a1.1 1.1 0 0 0-.9-1.1zM197.3 164.1l-.2 .4h1a.51 .51 0 0 0-.3-.5 .51 .51 0 0 0-.5 .1zM197.2 164l.4-.2 .4 .1 .2 .6h-1.2z"/>
<path d="M186.4 163.1a1.09 1.09 0 0 1 1.8 .6h-.3a.65 .65 0 0 0-.7-.5 .65 .65 0 0 0-.6 .5l.3 .3a1.12 1.12 0 0 1 1.4 1 1.16 1.16 0 0 1-1.2 .7 1.16 1.16 0 0 1-1-.9l.3-.1a.76 .76 0 0 0 .8 .7 .76 .76 0 0 0 .7-.6l-.4-.3a1.03 1.03 0 0 1-1.2-1.3zM188.7 163.7h.4v1.1a.5 .5 0 0 0 .5 .6 .5 .5 0 0 0 .4-.7v-1h.3v2h-.3v-.3a.71 .71 0 0 1-.8 .3 .71 .71 0 0 1-.5-.8zM190.9 162.9h.3v1a.88 .88 0 0 1 1.1-.1 .88 .88 0 0 1 .3 1.1 .79 .79 0 0 1-.6 .8 .79 .79 0 0 1-.8-.3v.3h-.3zM191.3 164.1a.73 .73 0 0 0-.1 .9 .73 .73 0 0 0 .8 .3 .74 .74 0 0 0 .3-.9 .74 .74 0 0 0-.8-.4zM193.1 163.2l.3-.2v.7h.4v.2h-.4v1.2l.1 .2 .3 .1v.3a.5 .5 0 0 1-.6-.1 .5 .5 0 0 1-.1-.5v-1.2h-.3v-.2h.3zM194.1 162.9h.3v.4h-.3zM194.1 163.7h.3v2h-.3zM195 163.2l.3-.2v.7h.4v.2h-.4v1.2l.1 .2 .3 .1v.3a.5 .5 0 0 1-.6-.1 .5 .5 0 0 1-.1-.5v-1.2h-.3v-.2h.3zM196 162.9h.3v2.8h-.3zM197 163.9a.94 .94 0 0 1 1.1-.2 .94 .94 0 0 1 .4 1h-1.5a.59 .59 0 0 0 .5 .7 .59 .59 0 0 0 .7-.4l.3 .1a1 1 0 0 1-1.4 .5 1 1 0 0 1-.3-1.5zM197.2 164l-.1 .5h1.1a.56 .56 0 0 0-.3-.6 .56 .56 0 0 0-.7 .1z"/>
<path d="M148.9 188.8a1.12 1.12 0 0 1 1.9 .6h-.4a.64 .64 0 0 0-.6-.5 .64 .64 0 0 0-.7 .5l.6 .3a.93 .93 0 0 1 1.1 1 .93 .93 0 0 1-1.3 .7 .91 .91 0 0 1-.9-1h.3a.75 .75 0 0 0 .7 .6 .75 .75 0 0 0 .8-.5l-1.3-.6a.67 .67 0 0 1-.2-1.1zM149 188.8a.75 .75 0 0 0-.1 .8 .75 .75 0 0 0 .7 .4l.5 .2a.49 .49 0 0 1 .4 .7 .49 .49 0 0 1-.7 .2 .69 .69 0 0 1-.9-.7l-.3 .1a1.12 1.12 0 0 0 1 .9 1.12 1.12 0 0 0 1.2-.8l-.2-.4-.3-.3-1.2-.3a.63 .63 0 0 1 .4-.8 .63 .63 0 0 1 .8 .3l.1 .3h.3a1.02 1.02 0 0 0-1.7-.6zM151.4 189.5a.84 .84 0 0 1 .9-.2 .84 .84 0 0 1 .5 .7h-.3a.53 .53 0 0 0-.7-.3 .53 .53 0 0 0-.3 .7 .52 .52 0 0 0 .4 .7 .52 .52 0 0 0 .6-.5h.4a.94 .94 0 0 1-1.2 .9 .94 .94 0 0 1-.6-1.3zM151.5 189.6a.97 .97 0 0 0-.2 1.4 .97 .97 0 0 0 1.4 0l.2-.3-.4-.1a.58 .58 0 0 1-.7 .6 .58 .58 0 0 1-.4-.8 .59 .59 0 0 1 .4-.8 .59 .59 0 0 1 .8 .4l.2-.1a.85 .85 0 0 0-1.3-.3zM153.3 189.6a.88 .88 0 0 1 1-.4 .88 .88 0 0 1 .6 .9l.1 1.3h-.4l-.1-.3a.73 .73 0 0 1-1 .3 .73 .73 0 0 1-.2-1.1l1.1-.2a.49 .49 0 0 0-.4-.5 .49 .49 0 0 0-.5 .4h-.4zM153.3 189.6l-.1 .3 .3 .1a.52 .52 0 0 1 .4-.4 .52 .52 0 0 1 .5 .1l.1 .4-.9 .2a.6 .6 0 0 0-.3 .9 .99 .99 0 0 0 1.3-.2v.4h.3l-.1-.4v-1.2a.97 .97 0 0 0-1.5-.2zM153.6 190.6l-.1 .1a.43 .43 0 0 0 .4 .5 .43 .43 0 0 0 .5-.4l.1-.4zM153.5 190.6l1-.3a.57 .57 0 0 1-.3 .8 .57 .57 0 0 1-.8-.4zM155.3 188.6h.4v2.8h-.4zM155.3 188.6v2.8h.4v-2.8zM156.3 189.6a.96 .96 0 0 1 1.2-.2 .96 .96 0 0 1 .4 1.1l-1.4-.1a.56 .56 0 0 0 .4 .7 .56 .56 0 0 0 .7-.4h.3a.83 .83 0 0 1-1.2 .7 1.16 1.16 0 0 1-.4-1.8zM156.4 189.6a1 1 0 0 0-.1 1.4 1 1 0 0 0 1.4 .1l.2-.3-.3-.1a.59 .59 0 0 1-.8 .4 .59 .59 0 0 1-.4-.7l1.5 .1a1.1 1.1 0 0 0-.9-1.1zM156.6 189.8l-.2 .4h1.1a.51 .51 0 0 0-.3-.5 .51 .51 0 0 0-.6 .1zM156.6 189.7l.4-.1h.3l.3 .6h-1.2z"/>
<path d="M148.9 188.8a1.09 1.09 0 0 1 1.8 .6h-.3a.65 .65 0 0 0-.7-.5 .65 .65 0 0 0-.6 .5l.4 .3a1.12 1.12 0 0 1 1.3 1 1.16 1.16 0 0 1-1.2 .7 1.16 1.16 0 0 1-1-.9l.3-.1a.76 .76 0 0 0 .8 .7 .76 .76 0 0 0 .7-.6l-.4-.3a1.03 1.03 0 0 1-1.2-1.3zM151.4 189.5a.86 .86 0 0 1 1.4 .4l-.3 .1a.55 .55 0 0 0-.7-.4 .55 .55 0 0 0-.3 .8 .55 .55 0 0 0 .4 .7 .55 .55 0 0 0 .6-.5l.4 .1a.93 .93 0 0 1-1.3 .6 .93 .93 0 0 1-.4-1.3zM153.3 189.6a.87 .87 0 0 1 .9-.3 .87 .87 0 0 1 .6 .8l.1 1.3h-.3l-.1-.3a.74 .74 0 0 1-.9 .4 .74 .74 0 0 1-.4-.9l.4-.3 .9-.2a.51 .51 0 0 0-.5-.5 .51 .51 0 0 0-.5 .4l-.3-.1zM153.6 190.6a.36 .36 0 0 0 0 .5 .36 .36 0 0 0 .4 0l.4-.3 .1-.4zM155.3 188.6h.4v2.8h-.4zM156.3 189.6a.94 .94 0 0 1 1.1-.2 .94 .94 0 0 1 .5 1.1h-1.5a.59 .59 0 0 0 .5 .6 .59 .59 0 0 0 .7-.4l.3 .1a1 1 0 0 1-1.4 .5 1 1 0 0 1-.3-1.5zM156.6 189.8l-.2 .4h1.2a.56 .56 0 0 0-.4-.6 .56 .56 0 0 0-.6 .2z"/>
<path d="M148.1 196.9h1.5v.3l-.6-.1v1.6h-.3l.1-1.6-.7 .1zM148.2 196.9v.2h.6v1.6h.2l-.1-1.6h.7v-.2zM149.8 196.9h.3v.7a.47 .47 0 0 1 .5-.2 .47 .47 0 0 1 .3 .5v.8h-.3v-.8a.27 .27 0 0 0-.3-.3 .27 .27 0 0 0-.2 .4v.7h-.3zM149.8 196.9v1.8h.3l-.1-.7a.35 .35 0 0 1 .3-.5 .35 .35 0 0 1 .4 .4v.8h.2l-.1-.8a.43 .43 0 0 0-.3-.5 .43 .43 0 0 0-.5 .3l.1-.8zM151.2 196.9h.3v.3h-.3zM151.2 196.9v.3h.3v-.3zM151.2 197.4h.3v1.3h-.3zM151.2 197.4v1.3h.3v-1.3zM151.8 197.5l.2-.1a.47 .47 0 0 1 .8 .4h-.3a.23 .23 0 0 0-.2-.2 .23 .23 0 0 0-.3 .2l.3 .1a.48 .48 0 0 1 .5 .6 .48 .48 0 0 1-.8 .2l-.3-.4 .3-.1a.27 .27 0 0 0 .3 .3 .27 .27 0 0 0 .2-.3v.1a.55 .55 0 0 1-.6-.2 .55 .55 0 0 1-.1-.6zM151.9 197.6a.3 .3 0 0 0-.1 .3 .3 .3 0 0 0 .3 .2l.3 .1a.21 .21 0 0 1 .2 .2 .21 .21 0 0 1-.2 .2l-.4-.1-.1-.2h-.2a.5 .5 0 0 0 .6 .4 .5 .5 0 0 0 .4-.5l-.7-.4a.28 .28 0 0 1 .2-.3 .28 .28 0 0 1 .3 .3l.2-.1a.52 .52 0 0 0-.8-.1zM153.8 197.5a.45 .45 0 0 1 .7 .1v-.7h.3v1.8h-.3v-.2a.51 .51 0 0 1-.5 .2 .51 .51 0 0 1-.4-.5zM153.8 197.6a.56 .56 0 0 0-.1 .8 .56 .56 0 0 0 .9 0l-.1 .3h.3v-1.8h-.3l.1 .8a.45 .45 0 0 0-.8-.1zM154 197.7l-.1 .6 .2 .2a.4 .4 0 0 0 .4-.5 .4 .4 0 0 0-.5-.3zM153.9 197.7a.45 .45 0 0 1 .7 .3 .45 .45 0 0 1-.7 .4l-.1-.3zM155.1 197.4h.3v.2a.27 .27 0 0 1 .1-.3 .27 .27 0 0 1 .4 .2l-.1 .2-.4 .1v.9h-.3zM155.1 197.4v1.3h.2v-.7a.3 .3 0 0 1 .1-.3 .3 .3 0 0 1 .3 0l.1-.2-.3-.1-.2 .2v-.2zM156 197.5a.57 .57 0 0 1 .6-.2 .57 .57 0 0 1 .4 .6l.1 .8h-.3v-.2a.47 .47 0 0 1-.8 .2 .47 .47 0 0 1 .2-.8h.5a.31 .31 0 0 0-.3-.3 .31 .31 0 0 0-.3 .2h-.2zM156 197.6l-.1 .2h.2a.32 .32 0 0 1 .3-.3 .32 .32 0 0 1 .3 .1l.1 .3-.6 .1a.37 .37 0 0 0-.2 .6 .37 .37 0 0 0 .5 0l.3-.1v.2h.3l-.2-1a.57 .57 0 0 0-.9-.1zM156.2 198.2l-.1 .1a.31 .31 0 0 0 .3 .2 .31 .31 0 0 0 .3-.2l.1-.2zM156.1 198.2l.6-.2a.36 .36 0 0 1-.1 .6 .36 .36 0 0 1-.5-.4zM157.1 197.4h.3l.2 1 .3-1h.2l.3 1 .2-1h.3l-.4 1.3h-.3l-.2-1-.2 1h-.3zM157.1 197.4l.4 1.3h.2l.2-1 .3 1h.3l.4-1.3h-.2l-.3 1.2-.3-1.2h-.2l-.3 1-.3-1zM159 196.9h.3v.3h-.3zM159 196.9v.3h.2v-.3zM159 197.4h.3v1.3h-.3zM159 197.4v1.3h.2v-1.3zM159.5 197.4h.3v.2a.47 .47 0 0 1 .5-.2 .47 .47 0 0 1 .4 .5v.8h-.3v-.8a.26 .26 0 0 0-.2-.3 .26 .26 0 0 0-.3 .2l-.1 .9h-.3zM159.6 197.4v1.3h.2v-.9a.34 .34 0 0 1 .4-.3 .34 .34 0 0 1 .2 .4v.8h.2v-1a.44 .44 0 0 0-.5-.3 .44 .44 0 0 0-.4 .3l.1-.3zM161 197.5l.4-.2 .4 .3v-.2h.3v1.1a.6 .6 0 0 1-.5 .7 .6 .6 0 0 1-.7-.4h.3a.33 .33 0 0 0 .3 .2 .33 .33 0 0 0 .3-.2v-.3a.55 .55 0 0 1-.7 .2 .55 .55 0 0 1-.3-.7zM161.1 197.6a.56 .56 0 0 0-.1 .8 .56 .56 0 0 0 .8 0v.1a.4 .4 0 0 1-.1 .5 .4 .4 0 0 1-.5 0l-.3-.2a.54 .54 0 0 0 .7 .4 .54 .54 0 0 0 .4-.7v-1.1h-.2l.1 .3-.5-.3zM161.2 197.7v.5l.1 .2a.39 .39 0 0 0 .5-.4 .39 .39 0 0 0-.6-.3zM161.2 197.7a.45 .45 0 0 1 .7 .3 .45 .45 0 0 1-.7 .4l-.1-.4zM163 196.9h.3v.3h-.3zM163 196.9v.3h.3v-.3zM163 197.4h.3v1.3h-.3zM163 197.4v1.3h.3v-1.3zM163.6 197.5l.2-.1a.47 .47 0 0 1 .7 .4h-.2a.23 .23 0 0 0-.2-.2 .23 .23 0 0 0-.3 .2l.3 .1a.48 .48 0 0 1 .5 .6 .48 .48 0 0 1-.8 .2l-.3-.4 .3-.1a.27 .27 0 0 0 .2 .3 .27 .27 0 0 0 .3-.3v.1a.55 .55 0 0 1-.6-.2 .55 .55 0 0 1-.1-.6zM163.7 197.6a.3 .3 0 0 0-.1 .3 .3 .3 0 0 0 .3 .2l.3 .1a.21 .21 0 0 1 .2 .2 .21 .21 0 0 1-.2 .2l-.4-.1-.1-.2h-.2a.5 .5 0 0 0 .6 .4 .5 .5 0 0 0 .4-.5l-.7-.4a.28 .28 0 0 1 .2-.3 .28 .28 0 0 1 .3 .3l.2-.1a.52 .52 0 0 0-.8-.1zM165.4 198.1a.7 .7 0 0 1 1.4 0 .7 .7 0 0 1-1.4 0zM165.5 198.1a.61 .61 0 0 0 1.2 0 .61 .61 0 0 0-1.2 0zM165.8 197.7a.42 .42 0 0 0-.1 .6 .42 .42 0 0 0 .6 .1 .42 .42 0 0 0 .1-.6 .42 .42 0 0 0-.6-.1zM165.7 197.7a.47 .47 0 0 1 .7 .4 .47 .47 0 0 1-.7 .3l-.1-.3zM166.8 197.4h.3v1a.29 .29 0 0 0 .4 0 .29 .29 0 0 0 .1-.3v-.7h.3v1.3h-.3l.1-.2a.44 .44 0 0 1-.5 .3 .44 .44 0 0 1-.4-.4zM166.8 197.4l.1 1a.44 .44 0 0 0 .4 .3 .44 .44 0 0 0 .4-.3v.3h.2v-1.3h-.3l.1 .7a.36 .36 0 0 1-.3 .5 .36 .36 0 0 1-.4-.5v-.7zM168.2 197.4h.3v.2a.27 .27 0 0 1 .2-.3 .27 .27 0 0 1 .3 .2l-.1 .2-.4 .1v.9h-.3zM168.2 197.4v1.3h.2v-.7a.3 .3 0 0 1 .1-.3 .3 .3 0 0 1 .4 0v-.2l-.3-.1-.1 .2-.1-.2zM169.7 197.4h.3l-.1 .2a.54 .54 0 0 1 .7-.2 .54 .54 0 0 1 .3 .6 .58 .58 0 0 1-.3 .7 .58 .58 0 0 1-.7-.1l.1 .6h-.3zM169.7 197.4v1.8h.2v-.8a.54 .54 0 0 0 .7 0 .54 .54 0 0 0 .1-.7 .54 .54 0 0 0-.8-.1v.1v-.3zM170.1 197.7l-.1 .6 .1 .2a.43 .43 0 0 0 .5-.4 .43 .43 0 0 0-.4-.5zM170 197.7a.45 .45 0 0 1 .6 .4 .45 .45 0 0 1-.6 .4l-.1-.4zM171.1 197.4h.3v.2a.27 .27 0 0 1 .1-.3 .27 .27 0 0 1 .3 .2v.2l-.4 .1v.9h-.3zM171.1 197.4v1.3h.2v-.7a.3 .3 0 0 1 .1-.3 .3 .3 0 0 1 .3 0l.1-.2-.3-.1-.2 .2v-.2zM171.8 198.1a.7 .7 0 0 1 1.4 0 .7 .7 0 0 1-1.4 0zM171.9 198.1a.61 .61 0 0 0 1.2 0 .61 .61 0 0 0-1.2 0zM172.2 197.7a.42 .42 0 0 0-.1 .6 .42 .42 0 0 0 .6 .1 .42 .42 0 0 0 .1-.6 .42 .42 0 0 0-.6-.1zM172.2 197.7a.47 .47 0 0 1 .7 .4 .47 .47 0 0 1-.7 .3l-.2-.3zM173.2 197.4h.3v.2a.54 .54 0 0 1 .6-.2 .54 .54 0 0 1 .3 .6 .58 .58 0 0 1-.3 .7 .58 .58 0 0 1-.7-.1l.1 .6h-.3zM173.3 197.4v1.8h.2l-.1-.8a.54 .54 0 0 0 .8 0 .54 .54 0 0 0 0-.7 .54 .54 0 0 0-.7-.1l-.1 .1 .1-.3zM173.6 197.7l-.1 .6 .2 .2a.43 .43 0 0 0 .4-.4 .43 .43 0 0 0-.4-.5zM173.5 197.7a.45 .45 0 0 1 .7 .4 .45 .45 0 0 1-.7 .4l-.1-.4zM174.7 197.5a.62 .62 0 0 1 .8-.1 .62 .62 0 0 1 .3 .7h-.9a.35 .35 0 0 0 .2 .4 .35 .35 0 0 0 .4-.3l.3 .1a.58 .58 0 0 1-.4 .5 .58 .58 0 0 1-.7-.2l-.2-.5zM174.8 197.6a.62 .62 0 0 0 0 1 .62 .62 0 0 0 1-.3h-.3a.38 .38 0 0 1-.4 .3 .38 .38 0 0 1-.3-.5h.9a.56 .56 0 0 0-.2-.6 .56 .56 0 0 0-.7 .1zM175 197.7l-.2 .2h.7a.31 .31 0 0 0-.2-.3 .31 .31 0 0 0-.3 .1zM174.9 197.6h.5l.2 .4h-.8zM175.9 197.4h.3v.2a.27 .27 0 0 1 .2-.3 .27 .27 0 0 1 .3 .2l-.1 .2-.4 .1v.9h-.3zM176 197.4v1.3h.2v-.7a.3 .3 0 0 1 0-.3 .3 .3 0 0 1 .4 0l.1-.2-.3-.1-.2 .2v-.2zM176.8 197.1l.3-.2v.5h.2v.2h-.2v.8l.2 .1v.2a.36 .36 0 0 1-.4 0 .36 .36 0 0 1-.1-.4v-.7h-.2v-.2h.2zM176.8 197.1l.1 .4-.2-.1v.2l.2-.1v.8a.28 .28 0 0 0 .1 .3 .28 .28 0 0 0 .3 .1l-.3-.4v-.8l.3 .1v-.2l-.3 .1 .1-.5zM177.3 197.4h.3l.3 1.1 .4-1.1h.3l-.7 1.6-.2 .2h-.3v-.3h.3l.1-.2zM177.3 197.4l.6 1.3-.2 .3h-.3l.1 .2h.2l.8-1.8h-.2l-.4 1.1-.3-1.1zM178.7 197.4h.3v.3h-.3zM178.8 197.4v.3h.2v-.3zM178.7 198.4h.3v.5l-.2 .2-.1-.2 .2-.2h-.2zM178.8 198.4v.3h.1l-.1 .3 .2-.6zM180 196.9h.3v.3h-.3zM180 196.9v.3h.2v-.3zM180 197.4h.3v1.3h-.3zM180 197.4v1.3h.2v-1.3zM180.6 197.1l.3-.2v.5h.2v.2h-.2v.8l.2 .1v.2a.36 .36 0 0 1-.4 0 .36 .36 0 0 1-.1-.4v-.7h-.2v-.2h.2zM180.6 197.1l.1 .4-.2-.1v.2l.2-.1v.8a.28 .28 0 0 0 .1 .3 .28 .28 0 0 0 .3 .1l-.3-.4v-.8l.3 .1v-.2l-.3 .1 .1-.5zM182 197.5a.55 .55 0 0 1 .6-.2 .55 .55 0 0 1 .4 .5l-.3 .1a.31 .31 0 0 0-.3-.3 .31 .31 0 0 0-.3 .2v.5a.29 .29 0 0 0 .4 .2 .29 .29 0 0 0 .2-.3h.3a.61 .61 0 0 1-.8 .5 .61 .61 0 0 1-.4-.8zM182 197.6a.6 .6 0 0 0 .1 1 .6 .6 0 0 0 .9-.3l-.2-.1a.35 .35 0 0 1-.4 .4 .35 .35 0 0 1-.3-.3v-.5a.34 .34 0 0 1 .3-.3 .34 .34 0 0 1 .3 .3h.2a.54 .54 0 0 0-.9-.2zM183.2 197.5a.57 .57 0 0 1 .6-.2 .57 .57 0 0 1 .4 .6l.1 .8h-.3v-.2a.47 .47 0 0 1-.8 .2 .47 .47 0 0 1 .2-.8h.5a.31 .31 0 0 0-.3-.3 .31 .31 0 0 0-.3 .2h-.2zM183.2 197.6l-.1 .2h.2a.32 .32 0 0 1 .3-.3 .32 .32 0 0 1 .3 .1l.1 .3-.6 .1a.37 .37 0 0 0-.2 .6 .37 .37 0 0 0 .5 0l.3-.1v.2h.3l-.2-1a.57 .57 0 0 0-.9-.1zM183.4 198.2v.1a.31 .31 0 0 0 .2 .2 .31 .31 0 0 0 .3-.2l.1-.2zM183.4 198.2l.6-.2a.36 .36 0 0 1-.2 .6 .36 .36 0 0 1-.5-.4zM184.4 197.4h.3v.2a.47 .47 0 0 1 .6-.2 .47 .47 0 0 1 .3 .5v.8h-.3v-.8a.26 .26 0 0 0-.2-.3 .26 .26 0 0 0-.3 .2l-.1 .9h-.3zM184.5 197.4v1.3h.2v-.9a.34 .34 0 0 1 .4-.3 .34 .34 0 0 1 .2 .4v.8h.2v-1a.44 .44 0 0 0-.5-.3 .44 .44 0 0 0-.4 .3l.1-.3zM185.8 196.9h.3l-.1 .7h-.2zM185.8 196.9l.1 .7h.1l.1-.7zM186.4 197.1l.3-.2-.1 .5h.3v.2h-.3l.1 .8 .2 .1v.2a.36 .36 0 0 1-.4 0 .36 .36 0 0 1-.1-.4v-.7h-.2v-.2h.2zM186.4 197.1l.1 .4-.2-.1v.2l.2-.1v.8a.28 .28 0 0 0 0 .3 .28 .28 0 0 0 .4 .1l-.3-.4v-.8l.2 .1v-.2l-.2 .1v-.5zM187.6 196.9h.3v.7a.52 .52 0 0 1 .6-.2 .52 .52 0 0 1 .3 .5 .6 .6 0 0 1-.2 .7 .6 .6 0 0 1-.7 0v.1h-.3zM187.7 196.9v1.8h.2v-.3a.57 .57 0 0 0 .8 0 .57 .57 0 0 0-.1-.9h-.5l-.2 .2v-.8zM188 197.7a.4 .4 0 0 0-.1 .6 .4 .4 0 0 0 .5 .1v-.7l-.2-.1zM188 197.7a.44 .44 0 0 1 .6 .4 .44 .44 0 0 1-.7 .3zM189.2 197.5a.62 .62 0 0 1 .7-.1 .62 .62 0 0 1 .3 .7h-.9a.35 .35 0 0 0 .3 .4 .35 .35 0 0 0 .4-.3l.2 .1a.58 .58 0 0 1-.4 .5 .58 .58 0 0 1-.6-.2l-.2-.5zM189.2 197.6a.62 .62 0 0 0 .1 1 .62 .62 0 0 0 .9-.3h-.2a.38 .38 0 0 1-.5 .3 .38 .38 0 0 1-.3-.5h1a.56 .56 0 0 0-.3-.6 .56 .56 0 0 0-.7 .1zM189.4 197.7l-.1 .2h.6a.31 .31 0 0 0-.1-.3 .31 .31 0 0 0-.4 .1zM189.3 197.6h.5l.2 .4h-.8zM191 197.4h.3v.2a.27 .27 0 0 1 .2-.3 .27 .27 0 0 1 .3 .2l-.1 .2-.4 .1v.9h-.3zM191.1 197.4v1.3h.2l-.1-.7a.3 .3 0 0 1 .1-.3 .3 .3 0 0 1 .4 0l.1-.2-.3-.1-.2 .2v-.2zM192 197.5a.62 .62 0 0 1 .7-.1 .62 .62 0 0 1 .3 .7h-.9a.35 .35 0 0 0 .3 .4 .35 .35 0 0 0 .4-.3l.2 .1a.58 .58 0 0 1-.4 .5 .58 .58 0 0 1-.6-.2l-.2-.5zM192 197.6a.62 .62 0 0 0 .1 1 .62 .62 0 0 0 .9-.3h-.2a.38 .38 0 0 1-.5 .3 .38 .38 0 0 1-.3-.5h1a.56 .56 0 0 0-.3-.6 .56 .56 0 0 0-.7 .1zM192.2 197.7l-.1 .2h.6a.31 .31 0 0 0-.1-.3 .31 .31 0 0 0-.4 .1zM192.1 197.6h.5l.2 .4h-.8zM193.2 197.4h.3l-.1 .2a.54 .54 0 0 1 .7-.2 .54 .54 0 0 1 .3 .6 .58 .58 0 0 1-.3 .7 .58 .58 0 0 1-.7-.1l.1 .6h-.3zM193.2 197.4v1.8h.2v-.8a.54 .54 0 0 0 .7 0 .54 .54 0 0 0 .1-.7 .54 .54 0 0 0-.8-.1v.1v-.3zM193.6 197.7l-.1 .6 .1 .2a.43 .43 0 0 0 .5-.4 .43 .43 0 0 0-.4-.5zM193.5 197.7a.45 .45 0 0 1 .7 .4 .45 .45 0 0 1-.7 .4l-.1-.4zM194.6 197.4h.3v.2a.27 .27 0 0 1 .1-.3 .27 .27 0 0 1 .4 .2l-.1 .2-.4 .1v.9h-.3zM194.6 197.4v1.3h.2v-.7a.3 .3 0 0 1 .1-.3 .3 .3 0 0 1 .3 0l.1-.2-.3-.1-.2 .2v-.2zM195.3 198.1a.7 .7 0 0 1 1.4 0 .7 .7 0 0 1-1.4 0zM195.4 198.1a.61 .61 0 0 0 1.2 0 .61 .61 0 0 0-1.2 0zM195.7 197.7a.42 .42 0 0 0-.1 .6 .42 .42 0 0 0 .6 .1 .42 .42 0 0 0 .1-.6 .42 .42 0 0 0-.6-.1zM195.7 197.7a.47 .47 0 0 1 .7 .4 .47 .47 0 0 1-.7 .3l-.2-.3zM196.8 197.5a.45 .45 0 0 1 .8 .1l-.1-.7h.3v1.8h-.2v-.2a.51 .51 0 0 1-.6 .2 .51 .51 0 0 1-.3-.5zM196.9 197.6a.56 .56 0 0 0-.1 .8 .56 .56 0 0 0 .8 0v.3h.2v-1.8h-.2v.8a.45 .45 0 0 0-.7-.1zM197 197.7v.6l.1 .2a.4 .4 0 0 0 .5-.5 .4 .4 0 0 0-.6-.3zM197 197.7a.45 .45 0 0 1 .6 .3 .45 .45 0 0 1-.6 .4l-.1-.3zM198.1 197.4h.3l.1 1a.29 .29 0 0 0 .3 0 .29 .29 0 0 0 .1-.3v-.7h.3v1.3h-.2v-.2a.44 .44 0 0 1-.4 .3 .44 .44 0 0 1-.4-.4zM198.2 197.4v1a.44 .44 0 0 0 .4 .3 .44 .44 0 0 0 .4-.3v.3h.2v-1.3h-.2v.7a.36 .36 0 0 1-.3 .5 .36 .36 0 0 1-.4-.5l.1-.7zM199.6 197.5a.55 .55 0 0 1 .6-.2 .55 .55 0 0 1 .4 .5l-.2 .1a.31 .31 0 0 0-.3-.3 .31 .31 0 0 0-.3 .2v.5a.29 .29 0 0 0 .3 .2 .29 .29 0 0 0 .3-.3h.2a.61 .61 0 0 1-.8 .5 .61 .61 0 0 1-.3-.8zM199.7 197.6a.6 .6 0 0 0 0 1 .6 .6 0 0 0 .9-.3l-.2-.1a.35 .35 0 0 1-.3 .4 .35 .35 0 0 1-.4-.3v-.5a.34 .34 0 0 1 .3-.3 .34 .34 0 0 1 .4 .3h.2a.54 .54 0 0 0-.9-.2zM200.9 197.5a.62 .62 0 0 1 .7-.1 .62 .62 0 0 1 .3 .7h-.9a.35 .35 0 0 0 .3 .4 .35 .35 0 0 0 .4-.3l.2 .1a.58 .58 0 0 1-.4 .5 .58 .58 0 0 1-.6-.2l-.2-.5zM200.9 197.6a.62 .62 0 0 0 .1 1 .62 .62 0 0 0 .9-.3h-.2a.38 .38 0 0 1-.5 .3 .38 .38 0 0 1-.2-.5h.9a.56 .56 0 0 0-.3-.6 .56 .56 0 0 0-.7 .1zM201.1 197.7l-.1 .2h.6a.31 .31 0 0 0-.1-.3 .31 .31 0 0 0-.4 .1zM201.1 197.6h.4l.2 .4h-.8zM202.2 197.5a.45 .45 0 0 1 .7 .1v-.7h.3v1.8h-.3l.1-.2a.51 .51 0 0 1-.6 .2 .51 .51 0 0 1-.4-.5zM202.2 197.6a.56 .56 0 0 0-.1 .8 .56 .56 0 0 0 .9 0v.3h.2v-1.8h-.3l.1 .8a.45 .45 0 0 0-.8-.1zM202.4 197.7l-.1 .6 .2 .2a.4 .4 0 0 0 .4-.5 .4 .4 0 0 0-.5-.3zM202.3 197.7a.45 .45 0 0 1 .7 .3 .45 .45 0 0 1-.7 .4l-.1-.3zM204.1 198.1a.69 .69 0 0 1 1.3 0 .69 .69 0 0 1-1.3 0zM204.1 198.1a.65 .65 0 0 0 1.3 0 .65 .65 0 0 0-1.3 0zM204.5 197.7a.42 .42 0 0 0-.1 .6 .42 .42 0 0 0 .5 .1 .42 .42 0 0 0 .1-.6 .42 .42 0 0 0-.5-.1zM204.4 197.7a.47 .47 0 0 1 .7 .4 .47 .47 0 0 1-.7 .3l-.1-.3zM205.5 197.4h.2v.2a.27 .27 0 0 1 .2-.3 .27 .27 0 0 1 .3 .2l-.1 .2-.3 .1v.9h-.3zM205.5 197.4v1.3h.2v-.7a.3 .3 0 0 1 .1-.3 .3 .3 0 0 1 .3 0l.1-.2-.3-.1-.2 .2v-.2zM207 197.5a.55 .55 0 0 1 .6-.2 .55 .55 0 0 1 .4 .5l-.2 .1a.31 .31 0 0 0-.3-.3 .31 .31 0 0 0-.3 .2v.5a.29 .29 0 0 0 .3 .2 .29 .29 0 0 0 .3-.3h.2a.61 .61 0 0 1-.7 .5 .61 .61 0 0 1-.4-.8zM207.1 197.6a.6 .6 0 0 0 0 1 .6 .6 0 0 0 .9-.3l-.2-.1a.35 .35 0 0 1-.3 .4 .35 .35 0 0 1-.4-.3v-.5a.34 .34 0 0 1 .4-.3 .34 .34 0 0 1 .3 .3h.2a.54 .54 0 0 0-.9-.2zM208.1 198.1a.7 .7 0 0 1 1.4 0 .7 .7 0 0 1-1.4 0zM208.2 198.1a.61 .61 0 0 0 1.2 0 .61 .61 0 0 0-1.2 0zM208.5 197.7a.42 .42 0 0 0-.1 .6 .42 .42 0 0 0 .6 .1 .42 .42 0 0 0 .1-.6 .42 .42 0 0 0-.6-.1zM208.4 197.7a.47 .47 0 0 1 .8 .4 .47 .47 0 0 1-.8 .3l-.1-.3zM209.5 197.4h.3l-.1 .2a.43 .43 0 0 1 .4-.3 .43 .43 0 0 1 .4 .3 .43 .43 0 0 1 .5-.2 .43 .43 0 0 1 .3 .4v.9h-.3v-.8a.23 .23 0 0 0-.1-.3 .23 .23 0 0 0-.3 .2v.9h-.3v-.8a.23 .23 0 0 0-.3-.3 .23 .23 0 0 0-.2 .3v.8h-.3zM209.5 197.4v1.3h.3l-.1-.7a.33 .33 0 0 1 .2-.4 .33 .33 0 0 1 .4 .3v.8h.2v-.8a.33 .33 0 0 1 .2-.3 .33 .33 0 0 1 .4 .1v1h.2l-.1-.9a.39 .39 0 0 0-.3-.4 .39 .39 0 0 0-.4 .3 .41 .41 0 0 0-.4-.3 .41 .41 0 0 0-.4 .3v-.3zM211.6 197.4h.2v.2a.43 .43 0 0 1 .4-.3 .43 .43 0 0 1 .4 .3 .43 .43 0 0 1 .5-.2 .43 .43 0 0 1 .3 .4v.9h-.3v-.8a.23 .23 0 0 0-.2-.3 .23 .23 0 0 0-.3 .2v.9h-.3v-.8a.23 .23 0 0 0-.2-.3 .23 .23 0 0 0-.2 .3v.8h-.3zM211.6 197.4v1.3h.2v-.7a.33 .33 0 0 1 .2-.4 .33 .33 0 0 1 .4 .3v.8h.2l-.1-.8a.33 .33 0 0 1 .2-.3 .33 .33 0 0 1 .4 .1v1h.2v-.9a.39 .39 0 0 0-.3-.4 .39 .39 0 0 0-.5 .3 .41 .41 0 0 0-.4-.3 .41 .41 0 0 0-.3 .3v-.3zM213.6 197.4h.3l.1 1a.29 .29 0 0 0 .3 0 .29 .29 0 0 0 .1-.3v-.7h.3v1.3h-.2v-.2a.44 .44 0 0 1-.4 .3 .44 .44 0 0 1-.4-.4zM213.7 197.4v1a.44 .44 0 0 0 .4 .3 .44 .44 0 0 0 .5-.3l-.1 .3h.2v-1.3h-.2v.7a.36 .36 0 0 1-.3 .5 .36 .36 0 0 1-.4-.5l.1-.7zM215 197.4h.3v.2a.47 .47 0 0 1 .5-.2 .47 .47 0 0 1 .4 .5v.8h-.3v-.8a.26 .26 0 0 0-.2-.3 .26 .26 0 0 0-.3 .2l-.1 .9h-.3zM215.1 197.4v1.3h.2v-.9a.34 .34 0 0 1 .4-.3 .34 .34 0 0 1 .2 .4v.8h.2v-1a.44 .44 0 0 0-.5-.3 .44 .44 0 0 0-.4 .3l.1-.3zM216.4 196.9h.3v.3h-.3zM216.5 196.9v.3h.2v-.3zM216.4 197.4h.3v1.3h-.3zM216.5 197.4v1.3h.2v-1.3zM217.1 197.5a.55 .55 0 0 1 .6-.2 .55 .55 0 0 1 .4 .5l-.2 .1a.31 .31 0 0 0-.3-.3 .31 .31 0 0 0-.3 .2v.5a.29 .29 0 0 0 .3 .2 .29 .29 0 0 0 .3-.3h.2a.61 .61 0 0 1-.8 .5 .61 .61 0 0 1-.3-.8zM217.2 197.6a.6 .6 0 0 0 0 1 .6 .6 0 0 0 .9-.3l-.2-.1a.35 .35 0 0 1-.3 .4 .35 .35 0 0 1-.4-.3v-.5a.34 .34 0 0 1 .3-.3 .34 .34 0 0 1 .4 .3h.2a.54 .54 0 0 0-.9-.2zM218.3 197.5a.57 .57 0 0 1 .7-.2 .57 .57 0 0 1 .4 .6l.1 .8h-.4v-.2a.47 .47 0 0 1-.7 .2 .47 .47 0 0 1 .1-.8h.6a.31 .31 0 0 0-.3-.3 .31 .31 0 0 0-.3 .2h-.3zM218.4 197.6l-.1 .2h.2a.32 .32 0 0 1 .2-.3 .32 .32 0 0 1 .3 .1l.1 .3-.6 .1a.37 .37 0 0 0-.2 .6 .37 .37 0 0 0 .6 0l.3-.1v.2h.2l-.1-1a.57 .57 0 0 0-.9-.1zM218.5 198.2v.1a.31 .31 0 0 0 .3 .2 .31 .31 0 0 0 .3-.2v-.2zM218.5 198.2l.6-.2a.36 .36 0 0 1-.2 .6 .36 .36 0 0 1-.5-.4zM219.6 197.1l.3-.2v.5h.2v.2h-.2v.8l.2 .1v.2a.36 .36 0 0 1-.4 0 .36 .36 0 0 1-.1-.4v-.7h-.2v-.2h.2zM219.6 197.1l.1 .4-.2-.1v.2l.2-.1v.8a.28 .28 0 0 0 .1 .3 .28 .28 0 0 0 .3 .1l-.3-.4v-.8l.3 .1v-.2l-.3 .1 .1-.5zM220.3 197.5a.62 .62 0 0 1 .8-.1 .62 .62 0 0 1 .3 .7h-.9a.35 .35 0 0 0 .2 .4 .35 .35 0 0 0 .4-.3l.3 .1a.58 .58 0 0 1-.4 .5 .58 .58 0 0 1-.7-.2l-.1-.5zM220.4 197.6a.62 .62 0 0 0 0 1 .62 .62 0 0 0 1-.3h-.3a.38 .38 0 0 1-.4 .3 .38 .38 0 0 1-.3-.5h.9a.56 .56 0 0 0-.2-.6 .56 .56 0 0 0-.7 .1zM220.6 197.7l-.2 .2h.7a.31 .31 0 0 0-.2-.3 .31 .31 0 0 0-.3 .1zM220.5 197.6h.5l.2 .4h-.8zM221.6 197.5a.45 .45 0 0 1 .8 .1v-.7h.3v1.8h-.3v-.2a.51 .51 0 0 1-.6 .2 .51 .51 0 0 1-.3-.5zM221.7 197.6a.56 .56 0 0 0-.1 .8 .56 .56 0 0 0 .9 0l-.1 .3h.2v-1.8h-.2v.8a.45 .45 0 0 0-.7-.1zM221.9 197.7l-.1 .6 .2 .2a.4 .4 0 0 0 .4-.5 .4 .4 0 0 0-.5-.3zM221.8 197.7a.45 .45 0 0 1 .7 .3 .45 .45 0 0 1-.7 .4l-.1-.3zM223.4 197.4h.3l.3 1 .2-1h.3l.2 1 .3-1h.3l-.4 1.3h-.3l-.2-1-.3 1h-.2zM223.5 197.4l.4 1.3h.2l.2-1 .3 1h.2l.5-1.3h-.3l-.3 1.2-.2-1.2h-.2l-.3 1-.3-1zM225.3 196.9h.3v.3h-.3zM225.4 196.9v.3h.2v-.3zM225.3 197.4h.3v1.3h-.3zM225.4 197.4v1.3h.2v-1.3zM226 197.1l.3-.2-.1 .5h.3v.2h-.3l.1 .8 .2 .1v.2a.36 .36 0 0 1-.4 0 .36 .36 0 0 1-.1-.4v-.7h-.2v-.2h.2zM226 197.1v.4l-.2-.1v.2l.2-.1v.8a.28 .28 0 0 0 .1 .3 .28 .28 0 0 0 .4 .1l-.3-.4v-.8l.2 .1v-.2l-.2 .1v-.5zM226.6 196.9h.3l-.1 .7a.47 .47 0 0 1 .6-.2 .47 .47 0 0 1 .3 .5v.8h-.3v-.8a.27 .27 0 0 0-.3-.3 .27 .27 0 0 0-.2 .4v.7h-.3zM226.6 196.9v1.8h.2v-.7a.35 .35 0 0 1 .3-.5 .35 .35 0 0 1 .4 .4l-.1 .8h.3l-.1-.8a.43 .43 0 0 0-.3-.5 .43 .43 0 0 0-.5 .3v-.8zM227.9 198.1a.7 .7 0 0 1 1.4 0 .7 .7 0 0 1-1.4 0zM228 198.1a.61 .61 0 0 0 1.2 0 .61 .61 0 0 0-1.2 0zM228.3 197.7a.42 .42 0 0 0-.1 .6 .42 .42 0 0 0 .6 .1 .42 .42 0 0 0 .1-.6 .42 .42 0 0 0-.6-.1zM228.2 197.7a.47 .47 0 0 1 .8 .4 .47 .47 0 0 1-.8 .3l-.1-.3zM229.3 197.4h.3v1a.29 .29 0 0 0 .4 0 .29 .29 0 0 0 .1-.3v-.7h.3v1.3h-.3l.1-.2a.44 .44 0 0 1-.5 .3 .44 .44 0 0 1-.4-.4zM229.3 197.4l.1 1a.44 .44 0 0 0 .4 .3 .44 .44 0 0 0 .4-.3v.3h.2v-1.3h-.2v.7a.36 .36 0 0 1-.3 .5 .36 .36 0 0 1-.4-.5v-.7zM230.7 197.1l.3-.2v.5h.3v.2h-.3v.8l.2 .1 .1 .2a.36 .36 0 0 1-.4 0 .36 .36 0 0 1-.2-.4l.1-.7h-.2v-.2h.2zM230.8 197.1v.4l-.2-.1v.2l.2-.1v.8a.28 .28 0 0 0 .1 .3 .28 .28 0 0 0 .3 .1l-.2-.4v-.8l.2 .1v-.2l-.2 .1v-.5zM231.9 198.1a.7 .7 0 0 1 1.4 0 .7 .7 0 0 1-1.4 0zM232 198.1a.61 .61 0 0 0 1.2 0 .61 .61 0 0 0-1.2 0zM232.3 197.7a.42 .42 0 0 0-.1 .6 .42 .42 0 0 0 .6 .1 .42 .42 0 0 0 .1-.6 .42 .42 0 0 0-.6-.1zM232.3 197.7a.47 .47 0 0 1 .7 .4 .47 .47 0 0 1-.7 .3l-.1-.3zM233.3 197.4h.3l.1 1a.29 .29 0 0 0 .3 0 .29 .29 0 0 0 .2-.3v-.7h.3v1.3h-.3v-.2a.44 .44 0 0 1-.4 .3 .44 .44 0 0 1-.4-.4zM233.4 197.4v1a.44 .44 0 0 0 .5 .3 .44 .44 0 0 0 .4-.3l-.1 .3h.2v-1.3h-.2v.7a.36 .36 0 0 1-.3 .5 .36 .36 0 0 1-.4-.5l.1-.7zM234.7 197.4h.3v.2a.27 .27 0 0 1 .2-.3 .27 .27 0 0 1 .3 .2l-.1 .2-.4 .1v.9h-.3zM234.8 197.4v1.3h.2v-.7a.3 .3 0 0 1 0-.3 .3 .3 0 0 1 .4 0l.1-.2-.3-.1-.2 .2v-.2zM236.1 197.4h.3l.2 1 .3-1h.2l.3 1 .2-1h.3l-.4 1.3h-.3l-.2-1-.2 1h-.3zM236.1 197.4l.4 1.3h.2l.2-1 .3 1h.3l.4-1.3h-.2l-.3 1.2-.3-1.2h-.2l-.3 1-.3-1zM238 197.4h.2v.2a.27 .27 0 0 1 .2-.3 .27 .27 0 0 1 .3 .2l-.1 .2-.4 .1 .1 .9h-.3zM238 197.4v1.3h.2v-.7a.3 .3 0 0 1 0-.3 .3 .3 0 0 1 .4 0l.1-.2-.3-.1-.2 .2v-.2zM238.8 196.9h.3v.3h-.3zM238.8 196.9v.3h.2v-.3zM238.8 197.4h.3v1.3h-.3zM238.8 197.4v1.3h.2v-1.3zM239.4 197.1l.3-.2v.5h.2v.2h-.2v.8l.2 .1v.2a.36 .36 0 0 1-.4 0 .36 .36 0 0 1-.1-.4v-.7h-.2v-.2h.2zM239.4 197.1l.1 .4-.2-.1v.2l.2-.1v.8a.28 .28 0 0 0 .1 .3 .28 .28 0 0 0 .3 .1l-.3-.4v-.8l.3 .1v-.2l-.3 .1 .1-.5zM240.1 197.1l.3-.2-.1 .5h.3v.2h-.3l.1 .8 .2 .1v.2a.36 .36 0 0 1-.4 0 .36 .36 0 0 1-.1-.4v-.7h-.2v-.2h.2zM240.1 197.1v.4l-.2-.1v.2l.2-.1v.8a.28 .28 0 0 0 .1 .3 .28 .28 0 0 0 .4 .1l-.3-.4v-.8l.2 .1v-.2l-.2 .1v-.5zM240.8 197.5a.62 .62 0 0 1 .8-.1 .62 .62 0 0 1 .2 .7h-.9a.35 .35 0 0 0 .3 .4 .35 .35 0 0 0 .4-.3l.2 .1a.58 .58 0 0 1-.4 .5 .58 .58 0 0 1-.6-.2l-.2-.5zM240.8 197.6a.62 .62 0 0 0 .1 1 .62 .62 0 0 0 .9-.3h-.2a.38 .38 0 0 1-.5 .3 .38 .38 0 0 1-.2-.5h.9a.56 .56 0 0 0-.3-.6 .56 .56 0 0 0-.7 .1zM241 197.7l-.1 .2h.7a.31 .31 0 0 0-.2-.3 .31 .31 0 0 0-.4 .1zM241 197.6h.4l.2 .4h-.8zM242 197.4h.3l-.1 .2a.47 .47 0 0 1 .6-.2 .47 .47 0 0 1 .3 .5v.8h-.3v-.8a.26 .26 0 0 0-.2-.3 .26 .26 0 0 0-.3 .2v.9h-.3zM242 197.4v1.3h.3l-.1-.9a.34 .34 0 0 1 .4-.3 .34 .34 0 0 1 .3 .4v.8h.2l-.1-1a.44 .44 0 0 0-.4-.3 .44 .44 0 0 0-.4 .3v-.3zM244.2 197.5a.55 .55 0 0 1 .5-.2 .55 .55 0 0 1 .4 .5l-.2 .1a.31 .31 0 0 0-.3-.3 .31 .31 0 0 0-.3 .2v.5a.29 .29 0 0 0 .4 .2 .29 .29 0 0 0 .2-.3h.3a.61 .61 0 0 1-.8 .5 .61 .61 0 0 1-.4-.8zM244.2 197.6a.6 .6 0 0 0 0 1 .6 .6 0 0 0 .9-.3l-.2-.1a.35 .35 0 0 1-.3 .4 .35 .35 0 0 1-.4-.3v-.5a.34 .34 0 0 1 .4-.3 .34 .34 0 0 1 .3 .3h.2a.54 .54 0 0 0-.9-.2zM245.2 198.1a.7 .7 0 0 1 1.4 0 .7 .7 0 0 1-1.4 0zM245.3 198.1a.61 .61 0 0 0 1.2 0 .61 .61 0 0 0-1.2 0zM245.6 197.7a.42 .42 0 0 0-.1 .6 .42 .42 0 0 0 .6 .1 .42 .42 0 0 0 .1-.6 .42 .42 0 0 0-.6-.1zM245.6 197.7a.47 .47 0 0 1 .7 .4 .47 .47 0 0 1-.7 .3l-.2-.3zM246.6 197.4h.3l-.1 .2a.47 .47 0 0 1 .6-.2 .47 .47 0 0 1 .3 .5v.8h-.3v-.8a.26 .26 0 0 0-.2-.3 .26 .26 0 0 0-.3 .2v.9h-.3zM246.7 197.4v1.3h.2v-.9a.34 .34 0 0 1 .4-.3 .34 .34 0 0 1 .2 .4v.8h.2l-.1-1a.44 .44 0 0 0-.4-.3 .44 .44 0 0 0-.4 .3v-.3zM248.1 197.5l.2-.1a.47 .47 0 0 1 .7 .4h-.3a.23 .23 0 0 0-.2-.2 .23 .23 0 0 0-.2 .2l.2 .1a.48 .48 0 0 1 .6 .6 .48 .48 0 0 1-.8 .2l-.4-.4 .3-.1a.27 .27 0 0 0 .3 .3 .27 .27 0 0 0 .2-.3v.1a.55 .55 0 0 1-.6-.2 .55 .55 0 0 1 0-.6zM248.1 197.6a.3 .3 0 0 0 0 .3 .3 .3 0 0 0 .2 .2l.4 .1a.21 .21 0 0 1 .2 .2 .21 .21 0 0 1-.2 .2l-.4-.1-.1-.2h-.2a.5 .5 0 0 0 .5 .4 .5 .5 0 0 0 .4-.5l-.7-.4a.28 .28 0 0 1 .3-.3 .28 .28 0 0 1 .3 .3l.1-.1a.52 .52 0 0 0-.8-.1zM249.4 197.5a.62 .62 0 0 1 .7-.1 .62 .62 0 0 1 .3 .7h-.9a.35 .35 0 0 0 .3 .4 .35 .35 0 0 0 .4-.3l.2 .1a.58 .58 0 0 1-.4 .5 .58 .58 0 0 1-.6-.2l-.2-.5zM249.4 197.6a.62 .62 0 0 0 .1 1 .62 .62 0 0 0 .9-.3h-.2a.38 .38 0 0 1-.5 .3 .38 .38 0 0 1-.3-.5h1a.56 .56 0 0 0-.3-.6 .56 .56 0 0 0-.7 .1zM249.6 197.7l-.1 .2h.6a.31 .31 0 0 0-.2-.3 .31 .31 0 0 0-.3 .1zM249.5 197.6h.5l.2 .4h-.8zM250.6 197.4h.2v.2a.47 .47 0 0 1 .6-.2 .47 .47 0 0 1 .3 .5v.8h-.3v-.8a.26 .26 0 0 0-.2-.3 .26 .26 0 0 0-.3 .2v.9h-.3zM250.6 197.4v1.3h.2v-.9a.34 .34 0 0 1 .4-.3 .34 .34 0 0 1 .3 .4l-.1 .8h.3l-.1-1a.44 .44 0 0 0-.4-.3 .44 .44 0 0 0-.4 .3v-.3zM252 197.1l.3-.2v.5h.2v.2h-.2v.8l.2 .1v.2a.36 .36 0 0 1-.4 0 .36 .36 0 0 1-.1-.4l.1-.7h-.2v-.2h.2zM252.1 197.1v.4l-.2-.1v.2l.2-.1v.8a.28 .28 0 0 0 .1 .3 .28 .28 0 0 0 .3 .1l-.3-.4v-.8l.3 .1v-.2l-.3 .1 .1-.5zM252.7 198.4h.3v.3h-.3zM252.7 198.4v.3h.3v-.3z"/>
<path d="M148.2 196.9h1.4v.2h-.6v1.6h-.2v-1.6h-.6zM149.8 196.9h.3v.7a.46 .46 0 0 1 .5-.2 .46 .46 0 0 1 .3 .5v.8h-.2v-.8a.31 .31 0 0 0-.4-.3 .31 .31 0 0 0-.2 .4v.7h-.3zM151.2 196.9h.3v.3h-.3zM151.2 197.4h.3v1.3h-.3zM151.9 197.5l.2-.1a.5 .5 0 0 1 .7 .3l-.3 .1a.25 .25 0 0 0-.2-.3 .25 .25 0 0 0-.3 .3l.2 .1a.44 .44 0 0 1 .5 .2 .44 .44 0 0 1-.1 .6l-.7-.1-.2-.3h.2a.29 .29 0 0 0 .4 .3 .29 .29 0 0 0 .2-.4h-.1a.46 .46 0 0 1-.5-.1 .46 .46 0 0 1 0-.6zM153.8 197.6l.4-.2 .3 .2v-.7h.3v1.8h-.3v-.2a.62 .62 0 0 1-.8-.1 .62 .62 0 0 1 .1-.8zM154 197.7a.45 .45 0 0 0-.2 .6 .45 .45 0 0 0 .7 .1v-.7l-.3-.1zM155.1 197.4h.2v.2l.4-.2v.3a.29 .29 0 0 0-.3 0 .29 .29 0 0 0-.1 .3v.7h-.2zM156 197.6l.1-.1a.57 .57 0 0 1 .7-.1 .57 .57 0 0 1 .2 .8l.1 .5h-.3v-.2a.45 .45 0 0 1-.7 .2 .45 .45 0 0 1-.1-.6l.8-.2a.32 .32 0 0 0-.3-.4 .32 .32 0 0 0-.4 .3h-.2zM156.2 198.2a.31 .31 0 0 0 .2 .4 .31 .31 0 0 0 .4-.3v-.2zM157.1 197.4h.2l.3 1 .3-1h.2l.3 1 .3-1h.2l-.4 1.3h-.3l-.2-1-.3 1h-.2zM159 196.9h.2v.3h-.2zM159 197.4h.2v1.3h-.2zM159.6 197.4h.2v.2a.46 .46 0 0 1 .5-.2 .46 .46 0 0 1 .3 .5v.8h-.2v-.8a.3 .3 0 0 0-.2-.3 .3 .3 0 0 0-.4 .2v.9h-.2zM161 197.6l.3-.2 .5 .2v-.2h.2v1.1a.56 .56 0 0 1-.4 .7 .56 .56 0 0 1-.7-.4h.2a.36 .36 0 0 0 .5 .2 .36 .36 0 0 0 .2-.5 .61 .61 0 0 1-.8-.1 .61 .61 0 0 1 0-.8zM161.2 197.7a.44 .44 0 0 0-.1 .6 .44 .44 0 0 0 .6 .1 .44 .44 0 0 0 .1-.6 .44 .44 0 0 0-.6-.1zM163 196.9h.3v.3h-.3zM163 197.4h.3v1.3h-.3zM163.6 197.5l.2-.1a.5 .5 0 0 1 .7 .3l-.2 .1a.25 .25 0 0 0-.3-.3 .25 .25 0 0 0-.2 .3l.1 .1a.44 .44 0 0 1 .6 .2 .44 .44 0 0 1-.2 .6l-.6-.1-.2-.3h.2a.29 .29 0 0 0 .4 .3 .29 .29 0 0 0 .2-.4h-.1a.46 .46 0 0 1-.5-.1 .46 .46 0 0 1-.1-.6zM165.4 198.1a.65 .65 0 0 1 1.3 0 .65 .65 0 0 1-1.3 0zM165.8 197.7a.44 .44 0 0 0-.1 .7 .44 .44 0 0 0 .7-.1l-.1-.6-.3-.1zM166.8 197.4h.2v.7a.32 .32 0 0 0 .4 .4 .32 .32 0 0 0 .2-.4v-.7h.3v1.3h-.2v-.2a.46 .46 0 0 1-.6 .2 .46 .46 0 0 1-.3-.5zM168.2 197.4h.2v.2l.4-.2 .1 .3a.29 .29 0 0 0-.4 0 .29 .29 0 0 0-.1 .3v.7h-.2zM169.7 197.4h.2v.2a.59 .59 0 0 1 .9 .5 .59 .59 0 0 1-.9 .5v.6h-.2zM170 197.7l-.1 .6 .2 .2a.47 .47 0 0 0 .5-.4 .47 .47 0 0 0-.5-.5zM171.1 197.4h.2v.2l.4-.2v.3a.29 .29 0 0 0-.3 0 .29 .29 0 0 0-.1 .3v.7h-.2zM171.9 198.1a.65 .65 0 0 1 1.3 0 .65 .65 0 0 1-1.3 0zM172.2 197.7a.44 .44 0 0 0-.1 .7 .44 .44 0 0 0 .7-.1l-.1-.6-.2-.1zM173.3 197.4h.2v.2a.59 .59 0 0 1 .9 .5 .59 .59 0 0 1-.9 .5v.6h-.2zM173.6 197.7l-.1 .6 .2 .2a.47 .47 0 0 0 .5-.4 .47 .47 0 0 0-.5-.5zM174.8 197.6a.6 .6 0 0 1 .7-.2 .6 .6 0 0 1 .3 .7h-1a.37 .37 0 0 0 .3 .4 .37 .37 0 0 0 .4-.2h.3a.65 .65 0 0 1-1 .3 .65 .65 0 0 1 0-1zM174.9 197.7l-.1 .2h.7l-.2-.3zM176 197.4h.2v.2l.4-.2v.3a.29 .29 0 0 0-.3 0 .29 .29 0 0 0-.1 .3v.7h-.2zM176.8 197.1l.3-.1v.4h.2v.2h-.2v.7l.2 .4a.32 .32 0 0 1-.3 0 .32 .32 0 0 1-.2-.4v-.7h-.1zM177.3 197.4h.3l.3 1.1 .4-1.1h.2l-.5 1.3a.45 .45 0 0 1-.5 .5l-.1-.2h.3l.1-.3zM178.8 197.4h.2v.3h-.2zM178.8 198.4h.2v.4l-.2 .2zM180 196.9h.2v.3h-.2zM180 197.4h.2v1.3h-.2zM180.6 197.1l.3-.1v.4h.2v.2h-.2v.7l.2 .4a.32 .32 0 0 1-.4 0 .32 .32 0 0 1-.1-.4v-.7h-.1zM182 197.6l.6-.2 .3 .4h-.2l-.1-.2a.44 .44 0 0 0-.5 .5 .44 .44 0 0 0 .5 .4l.2-.3 .2 .1a.61 .61 0 0 1-.9 .3 .61 .61 0 0 1-.2-.9zM183.2 197.6l.1-.1a.57 .57 0 0 1 .7-.1 .57 .57 0 0 1 .2 .8l.1 .5h-.3v-.2a.45 .45 0 0 1-.7 .2 .45 .45 0 0 1-.1-.6l.8-.2a.32 .32 0 0 0-.3-.4 .32 .32 0 0 0-.4 .3h-.2zM183.4 198.2a.31 .31 0 0 0 .2 .4 .31 .31 0 0 0 .4-.3v-.2zM184.5 197.4h.2v.2a.46 .46 0 0 1 .5-.2 .46 .46 0 0 1 .3 .5v.8h-.2v-.8a.3 .3 0 0 0-.2-.3 .3 .3 0 0 0-.4 .2v.9h-.2zM185.8 196.9h.3l-.1 .7h-.1zM186.4 197.1l.2-.1v.4h.2v.2h-.2v.7l.3 .4a.32 .32 0 0 1-.4 0 .32 .32 0 0 1-.1-.4v-.7h-.1zM187.7 196.9h.2v.7a.59 .59 0 0 1 .9 .5 .59 .59 0 0 1-.9 .4v.2h-.2zM188 197.7a.44 .44 0 0 0-.1 .6 .44 .44 0 0 0 .6 .1v-.7l-.3-.1zM189.2 197.6a.6 .6 0 0 1 .7-.2 .6 .6 0 0 1 .3 .7h-1a.37 .37 0 0 0 .3 .4 .37 .37 0 0 0 .5-.2h.2a.65 .65 0 0 1-1 .3 .65 .65 0 0 1 0-1zM189.4 197.7l-.1 .2h.7l-.2-.3zM191.1 197.4h.2v.2l.4-.2v.3a.29 .29 0 0 0-.3 0 .29 .29 0 0 0-.1 .3v.7h-.2zM192 197.6a.6 .6 0 0 1 .7-.2 .6 .6 0 0 1 .3 .7h-1a.37 .37 0 0 0 .3 .4 .37 .37 0 0 0 .5-.2h.2a.65 .65 0 0 1-1 .3 .65 .65 0 0 1 0-1zM192.2 197.7l-.1 .2h.7l-.2-.3zM193.2 197.4h.2v.2a.59 .59 0 0 1 .9 .5 .59 .59 0 0 1-.9 .5v.6h-.2zM193.5 197.7l-.1 .6 .2 .2a.47 .47 0 0 0 .5-.4 .47 .47 0 0 0-.5-.5zM194.6 197.4h.2v.2l.4-.2v.3a.29 .29 0 0 0-.3 0 .29 .29 0 0 0-.1 .3v.7h-.2zM195.4 198.1a.65 .65 0 0 1 1.3 0 .65 .65 0 0 1-1.3 0zM195.7 197.7a.44 .44 0 0 0-.1 .7 .44 .44 0 0 0 .7-.1l-.1-.6-.2-.1zM196.8 197.6l.4-.2 .4 .2v-.7h.2v1.8h-.2v-.2a.62 .62 0 0 1-.9-.1 .62 .62 0 0 1 .1-.8zM197 197.7a.45 .45 0 0 0-.1 .6 .45 .45 0 0 0 .6 .1v-.7l-.3-.1zM198.2 197.4h.2v.7a.32 .32 0 0 0 .3 .4 .32 .32 0 0 0 .3-.4v-.7h.2v1.3h-.2v-.2a.46 .46 0 0 1-.5 .2 .46 .46 0 0 1-.3-.5zM199.7 197.6l.6-.2 .3 .4h-.2l-.1-.2a.44 .44 0 0 0-.6 .5 .44 .44 0 0 0 .6 .4l.1-.3 .2 .1a.61 .61 0 0 1-.9 .3 .61 .61 0 0 1-.1-.9zM200.9 197.6a.6 .6 0 0 1 .7-.2 .6 .6 0 0 1 .3 .7h-.9a.37 .37 0 0 0 .2 .4 .37 .37 0 0 0 .5-.2h.2a.65 .65 0 0 1-1 .3 .65 .65 0 0 1 0-1zM201.1 197.7l-.1 .2h.7l-.2-.3zM202.2 197.6l.4-.2 .3 .2v-.7h.3v1.8h-.2v-.2a.62 .62 0 0 1-.9-.1 .62 .62 0 0 1 .1-.8zM202.4 197.7a.45 .45 0 0 0-.2 .6 .45 .45 0 0 0 .7 .1v-.7l-.3-.1zM204.1 198.1a.65 .65 0 0 1 1.3 0 .65 .65 0 0 1-1.3 0zM204.4 197.7a.44 .44 0 0 0 0 .7 .44 .44 0 0 0 .7-.1l-.1-.6-.3-.1zM205.5 197.4h.2v.2l.4-.2v.3a.29 .29 0 0 0-.3 0 .29 .29 0 0 0-.1 .3v.7h-.2zM207.1 197.6l.6-.2 .3 .4h-.2l-.1-.2a.44 .44 0 0 0-.6 .5 .44 .44 0 0 0 .6 .4l.1-.3 .2 .1a.61 .61 0 0 1-.8 .3 .61 .61 0 0 1-.2-.9zM208.1 198.1a.65 .65 0 0 1 1.3 0 .65 .65 0 0 1-1.3 0zM208.5 197.7a.44 .44 0 0 0-.1 .7 .44 .44 0 0 0 .7-.1l-.1-.6-.3-.1zM209.5 197.4h.2v.2a.43 .43 0 0 1 .8 0l.2-.2 .5 .1 .1 1.2h-.2v-.8a.27 .27 0 0 0-.2-.3 .27 .27 0 0 0-.4 .2v.9h-.2v-.8a.29 .29 0 0 0-.4-.3 .29 .29 0 0 0-.1 .4v.7h-.3zM211.6 197.4h.2v.2a.43 .43 0 0 1 .8 0l.2-.2 .4 .1 .1 1.2h-.2v-.8a.27 .27 0 0 0-.2-.3 .27 .27 0 0 0-.3 .2v.9h-.2v-.8a.29 .29 0 0 0-.4-.3 .29 .29 0 0 0-.2 .4v.7h-.2zM213.7 197.4h.2v.7a.32 .32 0 0 0 .3 .4 .32 .32 0 0 0 .3-.4v-.7h.2v1.3h-.2v-.2a.46 .46 0 0 1-.5 .2 .46 .46 0 0 1-.3-.5zM215.1 197.4h.2v.2a.46 .46 0 0 1 .5-.2 .46 .46 0 0 1 .3 .5v.8h-.2v-.8a.3 .3 0 0 0-.2-.3 .3 .3 0 0 0-.4 .2v.9h-.2zM216.5 196.9h.2v.3h-.2zM216.5 197.4h.2v1.3h-.2zM217.1 197.6l.7-.2 .3 .4h-.2l-.1-.2a.44 .44 0 0 0-.6 .5 .44 .44 0 0 0 .6 .4l.1-.3 .2 .1a.61 .61 0 0 1-.9 .3 .61 .61 0 0 1-.1-.9zM218.3 197.6l.1-.1a.57 .57 0 0 1 .8-.1 .57 .57 0 0 1 .1 .8l.1 .5h-.2l-.1-.2a.45 .45 0 0 1-.6 .2 .45 .45 0 0 1-.1-.6l.7-.2a.32 .32 0 0 0-.3-.4 .32 .32 0 0 0-.3 .3h-.2zM218.5 198.2a.31 .31 0 0 0 .3 .4 .31 .31 0 0 0 .3-.3v-.2zM219.6 197.1l.3-.1v.4h.2v.2h-.2v.7l.2 .4a.32 .32 0 0 1-.3 0 .32 .32 0 0 1-.2-.4v-.7h-.1zM220.4 197.6a.6 .6 0 0 1 .7-.2 .6 .6 0 0 1 .3 .7h-1a.37 .37 0 0 0 .3 .4 .37 .37 0 0 0 .4-.2h.3a.65 .65 0 0 1-1 .3 .65 .65 0 0 1 0-1zM220.5 197.7l-.1 .2h.7l-.2-.3zM221.7 197.6l.3-.2 .4 .2v-.7h.2v1.8h-.2v-.2a.62 .62 0 0 1-.8-.1 .62 .62 0 0 1 .1-.8zM221.8 197.7a.45 .45 0 0 0-.1 .6 .45 .45 0 0 0 .6 .1v-.7l-.2-.1zM223.5 197.4h.2l.3 1 .3-1h.2l.2 1 .3-1h.3l-.5 1.3h-.2l-.2-1-.3 1h-.2zM225.4 196.9h.2v.3h-.2zM225.4 197.4h.2v1.3h-.2zM226 197.1l.2-.1v.4h.2v.2h-.2v.7l.3 .4a.32 .32 0 0 1-.4 0 .32 .32 0 0 1-.1-.4v-.7h-.2zM226.6 196.9h.2v.7a.46 .46 0 0 1 .6-.2 .46 .46 0 0 1 .3 .5v.8h-.3v-.8a.31 .31 0 0 0-.3-.3 .31 .31 0 0 0-.3 .4v.7h-.2zM227.9 198.1a.65 .65 0 0 1 1.3 0 .65 .65 0 0 1-1.3 0zM228.3 197.7a.44 .44 0 0 0-.1 .7 .44 .44 0 0 0 .7-.1l-.1-.6-.3-.1zM229.3 197.4h.2v.7a.32 .32 0 0 0 .4 .4 .32 .32 0 0 0 .3-.4v-.7h.2v1.3h-.2v-.2a.46 .46 0 0 1-.6 .2 .46 .46 0 0 1-.3-.5zM230.8 197.1l.2-.1v.4h.2v.2h-.2v.7l.2 .4a.32 .32 0 0 1-.3 0 .32 .32 0 0 1-.1-.4v-.7h-.2zM232 198.1a.65 .65 0 0 1 1.3 0 .65 .65 0 0 1-1.3 0zM232.3 197.7a.44 .44 0 0 0-.1 .7 .44 .44 0 0 0 .7-.1l-.1-.6-.2-.1zM233.4 197.4h.2v.7a.32 .32 0 0 0 .3 .4 .32 .32 0 0 0 .3-.4v-.7h.2v1.3h-.2v-.2a.46 .46 0 0 1-.5 .2 .46 .46 0 0 1-.3-.5zM234.8 197.4h.2v.2l.4-.2v.3a.29 .29 0 0 0-.3 0 .29 .29 0 0 0-.1 .3v.7h-.2zM236.1 197.4h.2l.3 1 .3-1h.2l.3 1 .3-1h.2l-.4 1.3h-.3l-.2-1-.3 1h-.2zM238 197.4h.2v.2l.4-.2v.3a.29 .29 0 0 0-.3 0 .29 .29 0 0 0-.1 .3v.7h-.2zM238.8 196.9h.2v.3h-.2zM238.8 197.4h.2v1.3h-.2zM239.4 197.1l.3-.1v.4h.2v.2h-.2v.7l.2 .4a.32 .32 0 0 1-.4 0 .32 .32 0 0 1-.1-.4v-.7h-.1zM240.1 197.1l.2-.1v.4h.2v.2h-.2v.7l.3 .4a.32 .32 0 0 1-.4 0 .32 .32 0 0 1-.1-.4v-.7h-.2zM240.8 197.6a.6 .6 0 0 1 .7-.2 .6 .6 0 0 1 .3 .7h-.9a.37 .37 0 0 0 .3 .4 .37 .37 0 0 0 .4-.2h.2a.65 .65 0 0 1-1 .3 .65 .65 0 0 1 0-1zM241 197.7l-.1 .2h.7l-.2-.3zM242 197.4h.2v.2a.46 .46 0 0 1 .6-.2 .46 .46 0 0 1 .3 .5v.8h-.2v-.8a.3 .3 0 0 0-.3-.3 .3 .3 0 0 0-.3 .2v.9h-.3zM244.2 197.6l.6-.2 .3 .4h-.2l-.1-.2a.44 .44 0 0 0-.5 .5 .44 .44 0 0 0 .5 .4l.1-.3 .2 .1a.61 .61 0 0 1-.8 .3 .61 .61 0 0 1-.2-.9zM245.3 198.1a.65 .65 0 0 1 1.3 0 .65 .65 0 0 1-1.3 0zM245.6 197.7a.44 .44 0 0 0-.1 .7 .44 .44 0 0 0 .7-.1l-.1-.6-.2-.1zM246.7 197.4h.1v.2a.46 .46 0 0 1 .6-.2 .46 .46 0 0 1 .3 .5v.8h-.2v-.8a.3 .3 0 0 0-.2-.3 .3 .3 0 0 0-.4 .2v.9h-.2zM248.1 197.5l.2-.1a.5 .5 0 0 1 .7 .3l-.2 .1a.25 .25 0 0 0-.3-.3 .25 .25 0 0 0-.2 .3l.1 .1a.44 .44 0 0 1 .6 .2 .44 .44 0 0 1-.2 .6l-.7-.1-.1-.3h.2a.29 .29 0 0 0 .3 .3 .29 .29 0 0 0 .2-.4 .46 .46 0 0 1-.6-.1 .46 .46 0 0 1 0-.6zM249.4 197.6a.6 .6 0 0 1 .7-.2 .6 .6 0 0 1 .3 .7h-1a.37 .37 0 0 0 .3 .4 .37 .37 0 0 0 .5-.2h.2a.65 .65 0 0 1-1 .3 .65 .65 0 0 1 0-1zM249.6 197.7l-.1 .2h.7l-.2-.3zM250.6 197.4h.2v.2a.46 .46 0 0 1 .6-.2 .46 .46 0 0 1 .3 .5v.8h-.3v-.8a.3 .3 0 0 0-.2-.3 .3 .3 0 0 0-.3 .2l-.1 .9h-.2zM252.1 197.1l.2-.1v.4h.2v.2h-.2v.7l.2 .4a.32 .32 0 0 1-.3 0 .32 .32 0 0 1-.1-.4v-.7h-.2zM252.7 198.4h.3v.3h-.3z"/>
<path d="M166.7 188.5h.4l.6 2.5 .6-2.5h.5l.6 2.5 .5-2.5h.5l-.8 2.9h-.4l-.7-2.5-.6 2.5h-.5zM166.7 188.6l.8 2.8h.4l.6-2.5 .7 2.5h.3l.8-2.8h-.4l-.5 2.4-.6-2.4h-.5l-.6 2.4-.6-2.4zM170.8 189.6a.96 .96 0 0 1 1.2-.2 .96 .96 0 0 1 .4 1.1l-1.5-.1a.56 .56 0 0 0 .5 .7 .56 .56 0 0 0 .6-.4h.4a.83 .83 0 0 1-1.2 .7 1.16 1.16 0 0 1-.4-1.8zM170.8 189.6a1 1 0 0 0 0 1.4 1 1 0 0 0 1.4 .1l.2-.3-.4-.1a.59 .59 0 0 1-.7 .4 .59 .59 0 0 1-.4-.7h1.5a1.1 1.1 0 0 0-.9-1zM171.1 189.8l-.2 .4h1.1a.51 .51 0 0 0-.3-.5 .51 .51 0 0 0-.6 .1zM171.1 189.7l.4-.2 .3 .1 .3 .6h-1.2zM172.8 188.5h.4v.5h-.4zM172.8 188.6v.4h.3v-.4zM172.8 189.3h.4v2.1h-.4zM172.8 189.4v2h.3v-2zM173.8 189.5a.77 .77 0 0 1 1.2 .1l-.1-.3h.4v1.8a.91 .91 0 0 1-.7 1.1 .91 .91 0 0 1-1.1-.7h.4a.53 .53 0 0 0 .5 .4 .53 .53 0 0 0 .5-.4v-.4a.81 .81 0 0 1-.9 .3 .81 .81 0 0 1-.5-.8v-.6zM173.8 189.6a.93 .93 0 0 0-.2 1.2 .93 .93 0 0 0 1.3 .3h.1a.61 .61 0 0 1-.2 .7 .61 .61 0 0 1-.8 0l-.1-.2-.3-.1a.86 .86 0 0 0 1 .6 .86 .86 0 0 0 .6-1l.1-1.7h-.3v.3a.76 .76 0 0 0-1.2-.1zM174 189.8a.65 .65 0 0 0-.1 .9 .65 .65 0 0 0 .9 .2 .65 .65 0 0 0 .1-.9 .65 .65 0 0 0-.9-.2zM174 189.7a.74 .74 0 0 1 1.1 .5 .74 .74 0 0 1-.7 .9 .82 .82 0 0 1-.4-1.4zM175.7 188.5h.5l-.1 1.1a.73 .73 0 0 1 .9-.3 .73 .73 0 0 1 .5 .8v1.3h-.5v-1.3a.45 .45 0 0 0-.5-.4 .45 .45 0 0 0-.3 .6v1.1h-.5zM175.8 188.6v2.8h.3v-1.1a.53 .53 0 0 1 .4-.7 .53 .53 0 0 1 .6 .5v1.3h.3v-1.3a.69 .69 0 0 0-.5-.8 .69 .69 0 0 0-.8 .4v-1.1zM177.9 188.8l.5-.2-.1 .8 .4-.1v.4h-.4l.1 1.3h.3l.1 .4a.57 .57 0 0 1-.6-.1 .57 .57 0 0 1-.3-.5l.1-1.2-.3 .1v-.4l.3 .1zM178 188.9v.5h-.3v.2h.3v1.2a.46 .46 0 0 0 .2 .5 .46 .46 0 0 0 .5 0v-.2a.27 .27 0 0 1-.3 0 .27 .27 0 0 1-.1-.3v-1.2h.4v-.2h-.4v-.7z"/>
<path d="M166.7 188.6h.4l.6 2.4 .6-2.4h.5l.6 2.4 .5-2.4h.4l-.8 2.8h-.3l-.7-2.5-.6 2.5h-.4zM170.8 189.6a.94 .94 0 0 1 1.1-.2 .94 .94 0 0 1 .5 1h-1.5a.59 .59 0 0 0 .4 .7 .59 .59 0 0 0 .7-.4l.4 .1a1 1 0 0 1-1.4 .5 1 1 0 0 1-.3-1.5zM171.1 189.7l-.2 .5h1.1a.56 .56 0 0 0-.3-.6 .56 .56 0 0 0-.6 .1zM172.8 188.6h.3v.4h-.3zM172.8 189.4h.3v2h-.3zM173.8 189.5l.6-.2 .6 .3v-.2h.3v1.7a.88 .88 0 0 1-.7 1.1 .88 .88 0 0 1-1-.7l.3 .1a.57 .57 0 0 0 .7 .2 .57 .57 0 0 0 .3-.7 .97 .97 0 0 1-1.3-.2 .97 .97 0 0 1 .2-1.4zM174 189.8a.72 .72 0 0 0-.1 .9 .72 .72 0 0 0 .8 .3 .7 .7 0 0 0 .3-1 .7 .7 0 0 0-1-.2zM175.8 188.6h.3v1a.71 .71 0 0 1 .9-.3 .71 .71 0 0 1 .4 .8v1.3h-.3v-1.3a.49 .49 0 0 0-.6-.5 .49 .49 0 0 0-.4 .7v1.1h-.3zM178 188.9l.3-.2v.7h.4v.2h-.4v1.2l.1 .2 .3 .1v.3a.5 .5 0 0 1-.6-.1 .5 .5 0 0 1-.1-.5v-1.2h-.3v-.2h.3z"/>
<path d="M185.9 188.4h1.3l.6 .3a1.41 1.41 0 0 1 .4 1.5 1.17 1.17 0 0 1-1.3 1.1h-1zM185.9 188.5v2.7h1a1.42 1.42 0 0 0 1.2-1 1.42 1.42 0 0 0-.4-1.5l-.5-.2zM186.3 188.8v2.1h.6a1.08 1.08 0 0 0 .9-.9 1.08 1.08 0 0 0-.5-1.1zM186.2 188.7h.7a1.13 1.13 0 0 1 1 1 1.13 1.13 0 0 1-.7 1.2h-1zM188.6 189.2h.4v.3a.47 .47 0 0 1 .3-.4 .47 .47 0 0 1 .5 .2l-.1 .4-.4-.1-.2 .2-.1 1.5h-.4zM188.7 189.2v2h.3v-1a.46 .46 0 0 1 .1-.6 .46 .46 0 0 1 .5 0l.2-.3a.61 .61 0 0 0-.9 .2l.1-.3zM190.1 189.4a.88 .88 0 0 1 .9-.3 .88 .88 0 0 1 .7 .8l.1 1.4h-.5v-.3a.73 .73 0 0 1-1.1 .3 .73 .73 0 0 1-.1-1.1l1.1-.2a.49 .49 0 0 0-.4-.5 .49 .49 0 0 0-.5 .4l-.4-.1zM190.1 189.5l-.2 .3h.4a.52 .52 0 0 1 .3-.4 .52 .52 0 0 1 .6 .2l.1 .4-.9 .1a.6 .6 0 0 0-.3 1 .99 .99 0 0 0 1.2-.2l.1 .3h.3l-.1-.3v-1.3a.97 .97 0 0 0-1.5-.1zM190.4 190.5l-.1 .1a.43 .43 0 0 0 .4 .4 .43 .43 0 0 0 .5-.3l.1-.5zM190.3 190.4l1-.2a.57 .57 0 0 1-.3 .8 .57 .57 0 0 1-.8-.4zM191.8 189.2h.5l.4 1.6 .4-1.6h.4l.4 1.6 .4-1.6h.4l-.6 2.1h-.5l-.3-1.6-.4 1.6h-.4zM191.9 189.2l.6 2h.4l.3-1.5 .5 1.5h.3l.6-2h-.3l-.4 1.7-.4-1.7h-.4l-.5 1.6-.4-1.6zM194.8 188.4h.4v.5h-.4zM194.9 188.5v.4h.3v-.4zM194.8 189.2h.4v2.1h-.4zM194.9 189.2v2h.3v-2zM195.6 189.2h.4v.3a.73 .73 0 0 1 .9-.3 .73 .73 0 0 1 .5 .8v1.3h-.5v-1.3a.46 .46 0 0 0-.5-.5 .46 .46 0 0 0-.3 .6v1.2h-.5zM195.7 189.2v2h.3v-1.1a.53 .53 0 0 1 .4-.7 .53 .53 0 0 1 .6 .6v1.2h.3v-1.5a.73 .73 0 0 0-.7-.5 .73 .73 0 0 0-.7 .4l.1-.4zM198 189.4a.77 .77 0 0 1 1.2 .1l-.1-.3h.4v1.8a.91 .91 0 0 1-.7 1.1 .91 .91 0 0 1-1.1-.7h.4a.53 .53 0 0 0 .5 .4 .53 .53 0 0 0 .5-.4v-.4a.81 .81 0 0 1-.9 .2 .81 .81 0 0 1-.5-.7v-.7zM198 189.4a.93 .93 0 0 0-.2 1.3 .93 .93 0 0 0 1.3 .2l.1 .1a.61 .61 0 0 1-.2 .7 .61 .61 0 0 1-.8 0l-.1-.2-.3-.1a.86 .86 0 0 0 1 .6 .86 .86 0 0 0 .6-1l.1-1.8h-.3v.4a.76 .76 0 0 0-1.2-.2zM198.2 189.7a.65 .65 0 0 0-.1 .8 .65 .65 0 0 0 .9 .2 .65 .65 0 0 0 .1-.8 .65 .65 0 0 0-.9-.2zM198.2 189.6a.74 .74 0 0 1 1.1 .4 .74 .74 0 0 1-.7 1 .82 .82 0 0 1-.4-1.4zM201 189.2h.4l-.1 .3a.73 .73 0 0 1 .9-.3 .73 .73 0 0 1 .5 .8v1.3h-.4v-1.3a.46 .46 0 0 0-.5-.5 .46 .46 0 0 0-.4 .6v1.2h-.4zM201 189.2v2h.4l-.1-1.1a.53 .53 0 0 1 .5-.7 .53 .53 0 0 1 .6 .6l-.1 1.2h.4v-1.5a.73 .73 0 0 0-.7-.5 .73 .73 0 0 0-.7 .4v-.4zM203.1 189.2h.5l-.1 1.5a.49 .49 0 0 0 .7 .2 .49 .49 0 0 0 .2-.6v-1.1h.4v2.1h-.3v-.4a.73 .73 0 0 1-.7 .4 .73 .73 0 0 1-.6-.5zM203.2 189.2v1.3a.68 .68 0 0 0 .5 .8 .68 .68 0 0 0 .8-.5v.4h.3v-2h-.3v1.1a.55 .55 0 0 1-.5 .8 .55 .55 0 0 1-.5-.8v-1.1zM205.3 189.2h.4l-.1 .3a.68 .68 0 0 1 .6-.4 .68 .68 0 0 1 .7 .4h-.1a.67 .67 0 0 1 .8-.4 .67 .67 0 0 1 .5 .8v1.4h-.4v-1.3a.41 .41 0 0 0-.5-.5 .41 .41 0 0 0-.3 .6v1.2h-.4v-1.4a.42 .42 0 0 0-.6-.3 .42 .42 0 0 0-.2 .6v1.1h-.4zM205.3 189.2v2h.4l-.1-1a.5 .5 0 0 1 .3-.7 .5 .5 0 0 1 .7 .4l-.1 1.3h.4l-.1-1.1a.48 .48 0 0 1 .4-.7 .48 .48 0 0 1 .6 .6l-.1 1.2h.4l-.1-1.3a.62 .62 0 0 0-.5-.7 .62 .62 0 0 0-.7 .4 .65 .65 0 0 0-.6-.4 .65 .65 0 0 0-.6 .4v-.4zM208.4 188.4h.4v1.1a.78 .78 0 0 1 .8-.3 .78 .78 0 0 1 .6 .6 .96 .96 0 0 1-.2 1.2 .96 .96 0 0 1-1.3 0l.1 .3h-.4zM208.5 188.5v2.7h.3l-.1-.4a.83 .83 0 0 0 1.2 .3 .83 .83 0 0 0 .2-1.1 .76 .76 0 0 0-.5-.7 .76 .76 0 0 0-.8 .3v-1.1zM209 189.7a.71 .71 0 0 0-.2 .8 .71 .71 0 0 0 .7 .4 .74 .74 0 0 0 .3-.8 .74 .74 0 0 0-.7-.6zM208.9 189.6a.65 .65 0 0 1 .9 0 .65 .65 0 0 1 .1 .9 .53 .53 0 0 1-.4 .5 .53 .53 0 0 1-.6-.3l-.2-.5zM210.7 189.4a.96 .96 0 0 1 1.2-.1 .96 .96 0 0 1 .4 1.1l-1.4-.1a.56 .56 0 0 0 .4 .6 .56 .56 0 0 0 .7-.4l.3 .1a.83 .83 0 0 1-1.1 .7 1.16 1.16 0 0 1-.5-1.9zM210.8 189.5a1 1 0 0 0-.1 1.4 1 1 0 0 0 1.4 .1l.2-.4h-.3a.59 .59 0 0 1-.7 .4 .59 .59 0 0 1-.5-.7h1.5a1.1 1.1 0 0 0-.9-1.1zM211.1 189.6l-.2 .4h1a.51 .51 0 0 0-.3-.5 .51 .51 0 0 0-.5 .1zM211 189.6l.4-.2 .4 .1 .2 .6h-1.2zM212.7 189.2h.4v.3a.47 .47 0 0 1 .3-.4 .47 .47 0 0 1 .5 .2l-.2 .4-.3-.1-.3 .2v1.5h-.4zM212.7 189.2v2h.4l-.1-1a.46 .46 0 0 1 .2-.6 .46 .46 0 0 1 .5 0l.1-.3a.61 .61 0 0 0-.8 .2l.1-.3z"/>
<path d="M185.9 188.5h1a1.41 1.41 0 0 1 1.3 1.2 1.41 1.41 0 0 1-1 1.5h-1.3zM186.3 188.8v2.1h.6a1.06 1.06 0 0 0 .9-1.1 1.06 1.06 0 0 0-.9-1zM188.7 189.2h.3v.3l.2-.3h.4l.2 .1-.2 .3a.45 .45 0 0 0-.5 .1 .45 .45 0 0 0-.1 .5v1h-.3zM190.1 189.5a.87 .87 0 0 1 .9-.3 .87 .87 0 0 1 .6 .7l.1 1.3h-.3l-.1-.2a.74 .74 0 0 1-.9 .3 .74 .74 0 0 1-.5-.9l.5-.3 .9-.1a.51 .51 0 0 0-.5-.6 .51 .51 0 0 0-.5 .4h-.4zM190.3 190.5a.36 .36 0 0 0 0 .5 .36 .36 0 0 0 .5 0l.4-.3 .1-.5zM191.9 189.2h.3l.5 1.6 .4-1.6h.4l.4 1.6 .4-1.6h.3l-.6 2h-.3l-.4-1.5-.4 1.5h-.4zM194.9 188.5h.3v.4h-.3zM194.9 189.2h.3v2h-.3zM195.7 189.2h.3v.3a.72 .72 0 0 1 .9-.3 .72 .72 0 0 1 .4 .8v1.2h-.3v-1.2a.5 .5 0 0 0-.6-.5 .5 .5 0 0 0-.4 .6v1.1h-.3zM198 189.4l.6-.2 .6 .3v-.3h.3v1.8a.88 .88 0 0 1-.7 1 .88 .88 0 0 1-1-.6l.3 .1a.57 .57 0 0 0 .7 .2 .57 .57 0 0 0 .3-.7 .97 .97 0 0 1-1.3-.3 .97 .97 0 0 1 .2-1.3zM198.2 189.6a.72 .72 0 0 0-.2 .9 .72 .72 0 0 0 .9 .4 .7 .7 0 0 0 .3-1 .7 .7 0 0 0-1-.3zM201 189.2h.3v.3a.72 .72 0 0 1 .9-.3 .72 .72 0 0 1 .5 .8v1.2h-.4v-1.2a.5 .5 0 0 0-.5-.5 .5 .5 0 0 0-.4 .6v1.1h-.4zM203.2 189.2h.3v1.1a.5 .5 0 0 0 .5 .7 .5 .5 0 0 0 .5-.7v-1.1h.3v2h-.3v-.3a.71 .71 0 0 1-.9 .4 .71 .71 0 0 1-.4-.8zM205.3 189.2h.3v.3a.68 .68 0 0 1 1.2 0 .65 .65 0 0 1 .8-.3 .65 .65 0 0 1 .5 .7v1.3h-.4v-1.2a.45 .45 0 0 0-.5-.6 .45 .45 0 0 0-.3 .7v1.1h-.4v-1.3a.46 .46 0 0 0-.6-.4 .46 .46 0 0 0-.2 .7v1h-.4zM208.5 188.5h.3v1a.88 .88 0 0 1 1.1-.1 .88 .88 0 0 1 .3 1.1 .79 .79 0 0 1-.6 .7 .79 .79 0 0 1-.8-.2v.2h-.3zM208.9 189.7a.73 .73 0 0 0-.1 .8 .73 .73 0 0 0 .8 .4 .74 .74 0 0 0 .3-.9 .74 .74 0 0 0-.8-.5zM210.8 189.5a.94 .94 0 0 1 1.1-.2 .94 .94 0 0 1 .4 1h-1.5a.59 .59 0 0 0 .5 .7 .59 .59 0 0 0 .7-.4h.3a1 1 0 0 1-1.4 .6 1 1 0 0 1-.3-1.5zM211 189.6l-.1 .4h1.1a.56 .56 0 0 0-.3-.5 .56 .56 0 0 0-.7 .1zM212.7 189.2h.4v.3l.2-.3h.4l.1 .1-.1 .3a.45 .45 0 0 0-.5 .1 .45 .45 0 0 0-.1 .5v1h-.4z"/>
<path d="M248.7 188.8a1.12 1.12 0 0 1 1.9 .6h-.4a.64 .64 0 0 0-.6-.5 .64 .64 0 0 0-.7 .5l.6 .3a.93 .93 0 0 1 1.1 1 .93 .93 0 0 1-1.3 .7 .91 .91 0 0 1-.9-1h.3a.75 .75 0 0 0 .7 .6 .75 .75 0 0 0 .8-.5l-1.3-.6a.67 .67 0 0 1-.2-1.1zM248.8 188.8a.75 .75 0 0 0-.1 .8 .75 .75 0 0 0 .7 .4l.5 .2a.49 .49 0 0 1 .4 .7 .49 .49 0 0 1-.7 .2 .69 .69 0 0 1-.9-.7l-.3 .1a1.12 1.12 0 0 0 1 .9 1.12 1.12 0 0 0 1.2-.8l-.1-.4-.4-.3-1.2-.3a.63 .63 0 0 1 .4-.8 .63 .63 0 0 1 .8 .3l.1 .3h.3a1.02 1.02 0 0 0-1.7-.6zM251 188.6h.4v1a.73 .73 0 0 1 .8-.3 .73 .73 0 0 1 .5 .8v1.3h-.4v-1.3a.45 .45 0 0 0-.6-.4 .45 .45 0 0 0-.3 .6v1.1h-.4zM251 188.6v2.8h.4l-.1-1.1a.53 .53 0 0 1 .4-.7 .53 .53 0 0 1 .7 .5l-.1 1.3h.4l-.1-1.3a.69 .69 0 0 0-.5-.8 .69 .69 0 0 0-.8 .4l.1-1.1zM253.3 189.6a.96 .96 0 0 1 1.2-.2 .96 .96 0 0 1 .4 1.1l-1.4-.1a.56 .56 0 0 0 .4 .7 .56 .56 0 0 0 .7-.4h.3a.83 .83 0 0 1-1.2 .7 1.16 1.16 0 0 1-.4-1.8zM253.4 189.6a1 1 0 0 0-.1 1.4 1 1 0 0 0 1.4 .1l.2-.3-.4-.1a.59 .59 0 0 1-.7 .4 .59 .59 0 0 1-.4-.7l1.5 .1a1.1 1.1 0 0 0-.9-1.1zM253.6 189.8l-.2 .4h1.1a.51 .51 0 0 0-.3-.5 .51 .51 0 0 0-.6 .1zM253.6 189.7l.4-.1h.3l.3 .6h-1.2zM255.4 189.6a.96 .96 0 0 1 1.2-.2 .96 .96 0 0 1 .5 1.1l-1.5-.1a.56 .56 0 0 0 .4 .7 .56 .56 0 0 0 .7-.4h.4a.83 .83 0 0 1-1.2 .7 1.16 1.16 0 0 1-.5-1.8zM255.5 189.6a1 1 0 0 0-.1 1.4 1 1 0 0 0 1.4 .1l.2-.3-.3-.1a.59 .59 0 0 1-.7 .4 .59 .59 0 0 1-.4-.7l1.5 .1a1.1 1.1 0 0 0-1-1.1zM255.8 189.8l-.2 .4h1.1a.51 .51 0 0 0-.3-.5 .51 .51 0 0 0-.6 .1zM255.7 189.7l.4-.1h.4l.2 .6h-1.2zM257.5 188.8l.4-.2v.8l.3-.1v.4h-.3v1.3h.3l.1 .4a.57 .57 0 0 1-.6-.1 .57 .57 0 0 1-.2-.5v-1.2l-.3 .1v-.4l.3 .1zM257.5 188.9l.1 .5h-.3v.2h.3v1.2a.46 .46 0 0 0 .1 .5 .46 .46 0 0 0 .5 0v-.2a.27 .27 0 0 1-.3 0 .27 .27 0 0 1-.1-.3v-1.2h.4v-.2h-.4l.1-.7z"/>
<path d="M248.7 188.8a1.09 1.09 0 0 1 1.8 .6h-.3a.65 .65 0 0 0-.7-.5 .65 .65 0 0 0-.6 .5l.4 .3a1.12 1.12 0 0 1 1.3 1 1.16 1.16 0 0 1-1.2 .7 1.16 1.16 0 0 1-1-.9l.3-.1a.76 .76 0 0 0 .8 .7 .76 .76 0 0 0 .7-.6l-.4-.3a1.03 1.03 0 0 1-1.2-1.3zM251 188.6h.4v1a.71 .71 0 0 1 .8-.3 .71 .71 0 0 1 .5 .8v1.3h-.4v-1.3a.49 .49 0 0 0-.6-.5 .49 .49 0 0 0-.3 .7v1.1h-.4zM253.3 189.6a.94 .94 0 0 1 1.1-.2 .94 .94 0 0 1 .5 1.1h-1.5a.59 .59 0 0 0 .5 .6 .59 .59 0 0 0 .6-.4l.4 .1a1 1 0 0 1-1.4 .5 1 1 0 0 1-.3-1.5zM253.6 189.8l-.2 .4h1.2a.56 .56 0 0 0-.4-.6 .56 .56 0 0 0-.6 .2zM255.5 189.6a.94 .94 0 0 1 1.1-.2 .94 .94 0 0 1 .5 1.1h-1.5a.59 .59 0 0 0 .4 .6 .59 .59 0 0 0 .7-.4l.3 .1a1 1 0 0 1-1.4 .5 1 1 0 0 1-.3-1.5zM255.8 189.8l-.2 .4h1.1a.56 .56 0 0 0-.3-.6 .56 .56 0 0 0-.6 .2zM257.5 188.9l.4-.2v.7h.3v.2h-.3v1.2v.3h.3l.1 .3a.5 .5 0 0 1-.6-.1 .5 .5 0 0 1-.2-.5v-1.2h-.2v-.2h.2z"/>
</g>
<path d="M253.4 171h6.1v2.8h-3.9v1.7h1.6v1.5h-1.6v4h-2.2z" fill="none" stroke="#370700" stroke-width=".34"/>
<g fill="none" stroke="#000137" stroke-width=".34">
<path d="M257.7 174.3l1.4 .5 .5-.2 .4-1.5h.9l.5 1.4 .6 .2 1.3-.8 .6 .6-.6 1.4 .3 .5 1.4 .4 .1 .9-1.4 .5-.2 .6 .7 1.3-.5 .6-1.4-.6-.6 .3-.3 1.4-.9 .1-.5-1.4-.6-.2-1.3 .7-.7-.5 .7-1.4-.3-.5-1.5-.4v-.9l1.4-.5 .2-.6-.7-1.3z"/>
<circle cx="260.7" cy="177.5" r="1.57"/>
</g>
<path d="M156.4 123.1h.1" fill="none" stroke="#000" stroke-width=".21"/>
<path d="M131.7 120.8h8.7v-3h32v3h8.6l1.1 3h1.8l.5 2.5-.1 .7h-1.3v1.3h-53.3v-1.3h-1.3v-.7l.5-2.5h1.8z" fill-rule="evenodd" fill="#fff"/>
<path d="M156.4 123.1h.1" fill="none" stroke="#000" stroke-width=".21"/>
<path d="M131.7 120.8h49.3l1.1 3h-51.4z" fill-rule="evenodd" fill="#fff"/>
<path d="M156.4 123.1h.1" fill="none" stroke="#000" stroke-width=".21"/>
<g fill="#fff">
<path d="M128.9 123.8h55l.5 2.5h-56z" fill-rule="evenodd"/>
<path d="M140.4 117.8h32v3h-32z" fill-rule="evenodd"/>
<path d="M129.7 127h53.3v1.3h-53.3z" fill-rule="evenodd"/>
<path d="M128.4 126.3h56l-.1 .7h-55.9z" fill-rule="evenodd"/>
</g>
<path d="M128.4 126.3l.5-2.5h55l.5 2.5M128.4 126.3h56M128.4 126.3v.7h55.9l.1-.7M129.7 127v1.3h53.3v-1.3M130.7 123.8l1-3h49.3l1.1 3M140.4 120.8v-3h32v3" fill="none" stroke="#000" stroke-width=".25"/>
<path d="M172.4 117.8h86.8M205.3 117v26M221.3 116.3v25.5M234.2 113.9v29.7M245.6 110.8v32.3M258.2 107.8v30.5M156.4 123.1h.1M181 120.8h65.6M183 128.3h76.2M183.9 123.8h51.3M184.3 127h22.1M184.4 126.3h37.9" fill="none" stroke="#000" stroke-width=".21"/>
<path d="M257.3 112.8h1.7l-.8 5zM204.5 122h1.7l-.9 5zM205.3 128.3l.9 5h-1.7zM221.3 128.3l.8 5h-1.6zM220.5 121.3h1.6l-.8 5zM234.2 128.3l.8 5h-1.6zM233.4 118.8h1.6l-.8 5zM244.8 115.8h1.6l-.8 5zM245.6 128.3l.8 5h-1.6zM258.2 128.3l.8 5h-1.7z" fill="#000" stroke="#000" stroke-width=".21"/>
<path d="M138.6 47.8a25.1 25.1 0 0 1 27.4-5.4 25.1 25.1 0 0 1 15.4 23.1h-11.2a13.8 13.8 0 0 1-20.3 12.2 13.8 13.8 0 0 1-1.3-23.6 13.8 13.8 0 0 1 21.5 9.9l.1 1.5h-13.8h25a25.1 25.1 0 0 1-34.6 23.2 25.1 25.1 0 0 1-8.2-40.9z" fill-rule="evenodd" fill="#fff"/>
<path d="M156.4 65.5h.1" fill="none" stroke="#000" stroke-width=".21"/>
<circle cx="156.4" cy="65.5" r="28" fill="#fff"/>
<path d="M156.4 65.5h.1" fill="none" stroke="#000" stroke-width=".21"/>
<circle cx="156.4" cy="65.5" r="28" fill="#fff"/>
<path d="M156.4 65.5h.1" fill="none" stroke="#000" stroke-width=".21"/>
<circle cx="156.4" cy="65.5" r="26.6" fill="#fff"/>
<path d="M156.4 65.5h.1" fill="none" stroke="#000" stroke-width=".21"/>
<circle cx="156.4" cy="65.5" r="25.1" fill="#fff"/>
<path d="M156.4 65.5h.1" fill="none" stroke="#000" stroke-width=".21"/>
<circle cx="156.4" cy="65.5" r="13.8" fill="#fff"/>
<path d="M99.3 58.3l91.8 11.6M100.4 42.6l78 31.9M190.4 48.7l-88.3 43.6M156.4 65.5h.1M192.6 60.1l-93.6 14" fill="none" stroke="#000" stroke-width=".21"/>
<g fill="none" stroke="#000" stroke-width=".25">
<path d="M156.4 65.5h25M183 65.5h1.4"/>
<circle cx="156.4" cy="65.5" r="28"/>
<circle cx="156.4" cy="65.5" r="25.1"/>
<circle cx="156.4" cy="65.5" r="26.6"/>
<circle cx="156.4" cy="65.5" r="13.8"/>
</g>
<path d="M156.4 64.9v1.2zM155.7 65.5h1.3z" fill-rule="evenodd" fill="#000" stroke="#080808" stroke-width=".21"/>
<path d="M181.4 53.1l4.2-2.9 .7 1.5zM125 69.4l5 .1-4.8 1.5zM126.4 79.3l4.9-1.4-4.1 2.9zM126.6 60.9l4.9 1.5-5.1 .2zM139.3 57.6l4.3 2.7-4.9-1.1zM169.1 70.7l5 1.1-.7 1.6zM181.2 68.6l5.1-.2-.2 1.7zM182.7 61.6l4.8-1.6 .3 1.6z" fill="#000" stroke="#000" stroke-width=".21"/>
<use href="#words"/>
</svg>
